VERSION 5.7 ;
  NOWIREEXTENSIONATPIN ON ;
  DIVIDERCHAR "/" ;
  BUSBITCHARS "[]" ;
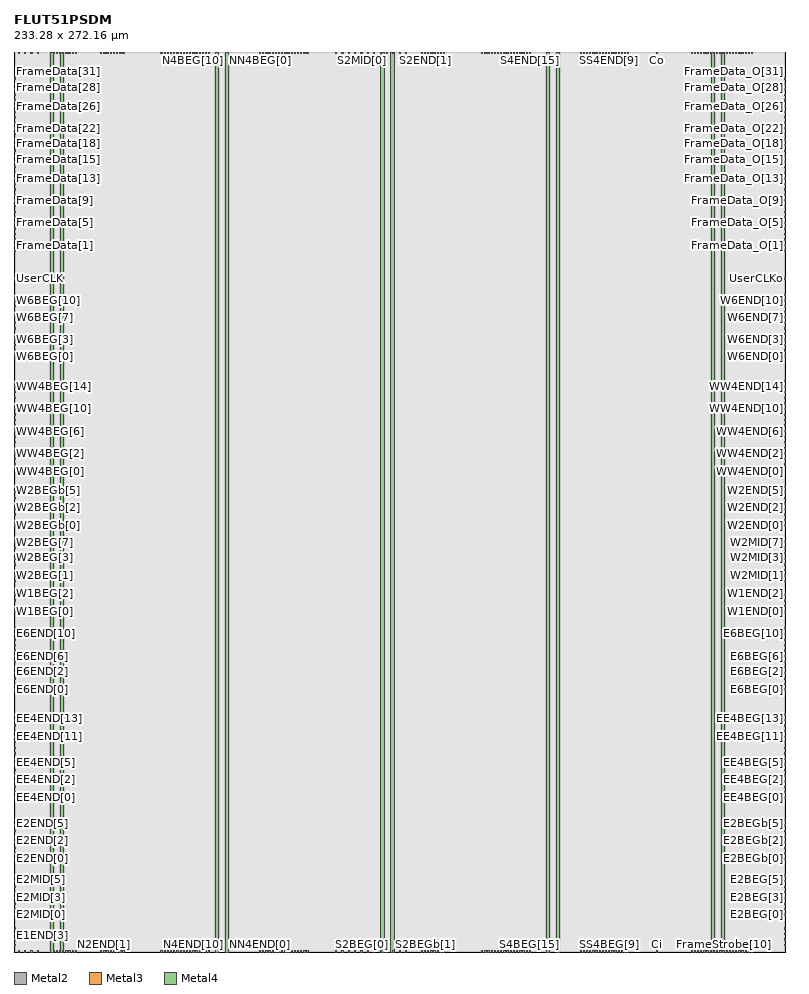
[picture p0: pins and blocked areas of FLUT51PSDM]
MACRO FLUT51PSDM
  CLASS BLOCK ;
  FOREIGN FLUT51PSDM ;
  ORIGIN 0.000 0.000 ;
  SIZE 233.280 BY 272.160 ;
  PIN Ci
    DIRECTION INPUT ;
    USE SIGNAL ;
    ANTENNAGATEAREA 0.241800 ;
    PORT
      LAYER Metal2 ;
        RECT 194.200 0.000 194.600 0.400 ;
    END
  END Ci
  PIN Co
    DIRECTION OUTPUT ;
    USE SIGNAL ;
    ANTENNADIFFAREA 2.647800 ;
    PORT
      LAYER Metal2 ;
        RECT 194.200 271.760 194.600 272.160 ;
    END
  END Co
  PIN E1BEG[0]
    DIRECTION OUTPUT ;
    USE SIGNAL ;
    ANTENNADIFFAREA 2.724000 ;
    PORT
      LAYER Metal3 ;
        RECT 232.880 1.900 233.280 2.300 ;
    END
  END E1BEG[0]
  PIN E1BEG[1]
    DIRECTION OUTPUT ;
    USE SIGNAL ;
    ANTENNADIFFAREA 2.724000 ;
    PORT
      LAYER Metal3 ;
        RECT 232.880 3.580 233.280 3.980 ;
    END
  END E1BEG[1]
  PIN E1BEG[2]
    DIRECTION OUTPUT ;
    USE SIGNAL ;
    ANTENNADIFFAREA 2.724000 ;
    PORT
      LAYER Metal3 ;
        RECT 232.880 5.260 233.280 5.660 ;
    END
  END E1BEG[2]
  PIN E1BEG[3]
    DIRECTION OUTPUT ;
    USE SIGNAL ;
    ANTENNADIFFAREA 2.724000 ;
    PORT
      LAYER Metal3 ;
        RECT 232.880 6.940 233.280 7.340 ;
    END
  END E1BEG[3]
  PIN E1END[0]
    DIRECTION INPUT ;
    USE SIGNAL ;
    ANTENNAGATEAREA 1.705600 ;
    PORT
      LAYER Metal3 ;
        RECT 0.000 1.900 0.400 2.300 ;
    END
  END E1END[0]
  PIN E1END[1]
    DIRECTION INPUT ;
    USE SIGNAL ;
    ANTENNAGATEAREA 2.132000 ;
    PORT
      LAYER Metal3 ;
        RECT 0.000 3.580 0.400 3.980 ;
    END
  END E1END[1]
  PIN E1END[2]
    DIRECTION INPUT ;
    USE SIGNAL ;
    ANTENNAGATEAREA 1.492400 ;
    PORT
      LAYER Metal3 ;
        RECT 0.000 5.260 0.400 5.660 ;
    END
  END E1END[2]
  PIN E1END[3]
    DIRECTION INPUT ;
    USE SIGNAL ;
    ANTENNAGATEAREA 2.145000 ;
    PORT
      LAYER Metal3 ;
        RECT 0.000 6.940 0.400 7.340 ;
    END
  END E1END[3]
  PIN E2BEG[0]
    DIRECTION OUTPUT ;
    USE SIGNAL ;
    ANTENNADIFFAREA 2.724000 ;
    PORT
      LAYER Metal3 ;
        RECT 232.880 11.140 233.280 11.540 ;
    END
  END E2BEG[0]
  PIN E2BEG[1]
    DIRECTION OUTPUT ;
    USE SIGNAL ;
    ANTENNADIFFAREA 2.724000 ;
    PORT
      LAYER Metal3 ;
        RECT 232.880 12.820 233.280 13.220 ;
    END
  END E2BEG[1]
  PIN E2BEG[2]
    DIRECTION OUTPUT ;
    USE SIGNAL ;
    ANTENNADIFFAREA 2.724000 ;
    PORT
      LAYER Metal3 ;
        RECT 232.880 14.500 233.280 14.900 ;
    END
  END E2BEG[2]
  PIN E2BEG[3]
    DIRECTION OUTPUT ;
    USE SIGNAL ;
    ANTENNADIFFAREA 2.724000 ;
    PORT
      LAYER Metal3 ;
        RECT 232.880 16.180 233.280 16.580 ;
    END
  END E2BEG[3]
  PIN E2BEG[4]
    DIRECTION OUTPUT ;
    USE SIGNAL ;
    ANTENNADIFFAREA 2.724000 ;
    PORT
      LAYER Metal3 ;
        RECT 232.880 17.860 233.280 18.260 ;
    END
  END E2BEG[4]
  PIN E2BEG[5]
    DIRECTION OUTPUT ;
    USE SIGNAL ;
    ANTENNADIFFAREA 2.724000 ;
    PORT
      LAYER Metal3 ;
        RECT 232.880 19.540 233.280 19.940 ;
    END
  END E2BEG[5]
  PIN E2BEG[6]
    DIRECTION OUTPUT ;
    USE SIGNAL ;
    ANTENNADIFFAREA 2.724000 ;
    PORT
      LAYER Metal3 ;
        RECT 232.880 21.220 233.280 21.620 ;
    END
  END E2BEG[6]
  PIN E2BEG[7]
    DIRECTION OUTPUT ;
    USE SIGNAL ;
    ANTENNADIFFAREA 2.724000 ;
    PORT
      LAYER Metal3 ;
        RECT 232.880 22.900 233.280 23.300 ;
    END
  END E2BEG[7]
  PIN E2BEGb[0]
    DIRECTION OUTPUT ;
    USE SIGNAL ;
    ANTENNADIFFAREA 2.724000 ;
    PORT
      LAYER Metal3 ;
        RECT 232.880 27.940 233.280 28.340 ;
    END
  END E2BEGb[0]
  PIN E2BEGb[1]
    DIRECTION OUTPUT ;
    USE SIGNAL ;
    ANTENNADIFFAREA 2.724000 ;
    PORT
      LAYER Metal3 ;
        RECT 232.880 29.620 233.280 30.020 ;
    END
  END E2BEGb[1]
  PIN E2BEGb[2]
    DIRECTION OUTPUT ;
    USE SIGNAL ;
    ANTENNADIFFAREA 2.724000 ;
    PORT
      LAYER Metal3 ;
        RECT 232.880 31.300 233.280 31.700 ;
    END
  END E2BEGb[2]
  PIN E2BEGb[3]
    DIRECTION OUTPUT ;
    USE SIGNAL ;
    ANTENNADIFFAREA 2.724000 ;
    PORT
      LAYER Metal3 ;
        RECT 232.880 32.980 233.280 33.380 ;
    END
  END E2BEGb[3]
  PIN E2BEGb[4]
    DIRECTION OUTPUT ;
    USE SIGNAL ;
    ANTENNADIFFAREA 2.724000 ;
    PORT
      LAYER Metal3 ;
        RECT 232.880 34.660 233.280 35.060 ;
    END
  END E2BEGb[4]
  PIN E2BEGb[5]
    DIRECTION OUTPUT ;
    USE SIGNAL ;
    ANTENNADIFFAREA 2.724000 ;
    PORT
      LAYER Metal3 ;
        RECT 232.880 36.340 233.280 36.740 ;
    END
  END E2BEGb[5]
  PIN E2BEGb[6]
    DIRECTION OUTPUT ;
    USE SIGNAL ;
    ANTENNADIFFAREA 2.724000 ;
    PORT
      LAYER Metal3 ;
        RECT 232.880 38.020 233.280 38.420 ;
    END
  END E2BEGb[6]
  PIN E2BEGb[7]
    DIRECTION OUTPUT ;
    USE SIGNAL ;
    ANTENNADIFFAREA 2.724000 ;
    PORT
      LAYER Metal3 ;
        RECT 232.880 39.700 233.280 40.100 ;
    END
  END E2BEGb[7]
  PIN E2END[0]
    DIRECTION INPUT ;
    USE SIGNAL ;
    ANTENNAGATEAREA 0.852800 ;
    PORT
      LAYER Metal3 ;
        RECT 0.000 27.940 0.400 28.340 ;
    END
  END E2END[0]
  PIN E2END[1]
    DIRECTION INPUT ;
    USE SIGNAL ;
    ANTENNAGATEAREA 1.279200 ;
    PORT
      LAYER Metal3 ;
        RECT 0.000 29.620 0.400 30.020 ;
    END
  END E2END[1]
  PIN E2END[2]
    DIRECTION INPUT ;
    USE SIGNAL ;
    ANTENNAGATEAREA 1.279200 ;
    PORT
      LAYER Metal3 ;
        RECT 0.000 31.300 0.400 31.700 ;
    END
  END E2END[2]
  PIN E2END[3]
    DIRECTION INPUT ;
    USE SIGNAL ;
    ANTENNAGATEAREA 1.492400 ;
    PORT
      LAYER Metal3 ;
        RECT 0.000 32.980 0.400 33.380 ;
    END
  END E2END[3]
  PIN E2END[4]
    DIRECTION INPUT ;
    USE SIGNAL ;
    ANTENNAGATEAREA 1.705600 ;
    PORT
      LAYER Metal3 ;
        RECT 0.000 34.660 0.400 35.060 ;
    END
  END E2END[4]
  PIN E2END[5]
    DIRECTION INPUT ;
    USE SIGNAL ;
    ANTENNAGATEAREA 1.492400 ;
    PORT
      LAYER Metal3 ;
        RECT 0.000 36.340 0.400 36.740 ;
    END
  END E2END[5]
  PIN E2END[6]
    DIRECTION INPUT ;
    USE SIGNAL ;
    ANTENNAGATEAREA 1.492400 ;
    PORT
      LAYER Metal3 ;
        RECT 0.000 38.020 0.400 38.420 ;
    END
  END E2END[6]
  PIN E2END[7]
    DIRECTION INPUT ;
    USE SIGNAL ;
    ANTENNAGATEAREA 1.066000 ;
    PORT
      LAYER Metal3 ;
        RECT 0.000 39.700 0.400 40.100 ;
    END
  END E2END[7]
  PIN E2MID[0]
    DIRECTION INPUT ;
    USE SIGNAL ;
    ANTENNAGATEAREA 2.099500 ;
    PORT
      LAYER Metal3 ;
        RECT 0.000 11.140 0.400 11.540 ;
    END
  END E2MID[0]
  PIN E2MID[1]
    DIRECTION INPUT ;
    USE SIGNAL ;
    ANTENNAGATEAREA 1.459900 ;
    PORT
      LAYER Metal3 ;
        RECT 0.000 12.820 0.400 13.220 ;
    END
  END E2MID[1]
  PIN E2MID[2]
    DIRECTION INPUT ;
    USE SIGNAL ;
    ANTENNAGATEAREA 1.673100 ;
    PORT
      LAYER Metal3 ;
        RECT 0.000 14.500 0.400 14.900 ;
    END
  END E2MID[2]
  PIN E2MID[3]
    DIRECTION INPUT ;
    USE SIGNAL ;
    ANTENNAGATEAREA 2.312700 ;
    PORT
      LAYER Metal3 ;
        RECT 0.000 16.180 0.400 16.580 ;
    END
  END E2MID[3]
  PIN E2MID[4]
    DIRECTION INPUT ;
    USE SIGNAL ;
    ANTENNAGATEAREA 1.673100 ;
    PORT
      LAYER Metal3 ;
        RECT 0.000 17.860 0.400 18.260 ;
    END
  END E2MID[4]
  PIN E2MID[5]
    DIRECTION INPUT ;
    USE SIGNAL ;
    ANTENNAGATEAREA 1.459900 ;
    PORT
      LAYER Metal3 ;
        RECT 0.000 19.540 0.400 19.940 ;
    END
  END E2MID[5]
  PIN E2MID[6]
    DIRECTION INPUT ;
    USE SIGNAL ;
    ANTENNAGATEAREA 1.699100 ;
    PORT
      LAYER Metal3 ;
        RECT 0.000 21.220 0.400 21.620 ;
    END
  END E2MID[6]
  PIN E2MID[7]
    DIRECTION INPUT ;
    USE SIGNAL ;
    ANTENNAGATEAREA 1.459900 ;
    PORT
      LAYER Metal3 ;
        RECT 0.000 22.900 0.400 23.300 ;
    END
  END E2MID[7]
  PIN E6BEG[0]
    DIRECTION OUTPUT ;
    USE SIGNAL ;
    ANTENNADIFFAREA 2.724000 ;
    PORT
      LAYER Metal3 ;
        RECT 232.880 79.180 233.280 79.580 ;
    END
  END E6BEG[0]
  PIN E6BEG[10]
    DIRECTION OUTPUT ;
    USE SIGNAL ;
    ANTENNADIFFAREA 2.724000 ;
    PORT
      LAYER Metal3 ;
        RECT 232.880 95.980 233.280 96.380 ;
    END
  END E6BEG[10]
  PIN E6BEG[11]
    DIRECTION OUTPUT ;
    USE SIGNAL ;
    ANTENNADIFFAREA 2.724000 ;
    PORT
      LAYER Metal3 ;
        RECT 232.880 97.660 233.280 98.060 ;
    END
  END E6BEG[11]
  PIN E6BEG[1]
    DIRECTION OUTPUT ;
    USE SIGNAL ;
    ANTENNADIFFAREA 2.724000 ;
    PORT
      LAYER Metal3 ;
        RECT 232.880 80.860 233.280 81.260 ;
    END
  END E6BEG[1]
  PIN E6BEG[2]
    DIRECTION OUTPUT ;
    USE SIGNAL ;
    ANTENNADIFFAREA 2.724000 ;
    PORT
      LAYER Metal3 ;
        RECT 232.880 82.540 233.280 82.940 ;
    END
  END E6BEG[2]
  PIN E6BEG[3]
    DIRECTION OUTPUT ;
    USE SIGNAL ;
    ANTENNADIFFAREA 2.724000 ;
    PORT
      LAYER Metal3 ;
        RECT 232.880 84.220 233.280 84.620 ;
    END
  END E6BEG[3]
  PIN E6BEG[4]
    DIRECTION OUTPUT ;
    USE SIGNAL ;
    ANTENNADIFFAREA 2.724000 ;
    PORT
      LAYER Metal3 ;
        RECT 232.880 85.900 233.280 86.300 ;
    END
  END E6BEG[4]
  PIN E6BEG[5]
    DIRECTION OUTPUT ;
    USE SIGNAL ;
    ANTENNADIFFAREA 2.724000 ;
    PORT
      LAYER Metal3 ;
        RECT 232.880 87.580 233.280 87.980 ;
    END
  END E6BEG[5]
  PIN E6BEG[6]
    DIRECTION OUTPUT ;
    USE SIGNAL ;
    ANTENNADIFFAREA 2.724000 ;
    PORT
      LAYER Metal3 ;
        RECT 232.880 89.260 233.280 89.660 ;
    END
  END E6BEG[6]
  PIN E6BEG[7]
    DIRECTION OUTPUT ;
    USE SIGNAL ;
    ANTENNADIFFAREA 2.724000 ;
    PORT
      LAYER Metal3 ;
        RECT 232.880 90.940 233.280 91.340 ;
    END
  END E6BEG[7]
  PIN E6BEG[8]
    DIRECTION OUTPUT ;
    USE SIGNAL ;
    ANTENNADIFFAREA 2.724000 ;
    PORT
      LAYER Metal3 ;
        RECT 232.880 92.620 233.280 93.020 ;
    END
  END E6BEG[8]
  PIN E6BEG[9]
    DIRECTION OUTPUT ;
    USE SIGNAL ;
    ANTENNADIFFAREA 2.724000 ;
    PORT
      LAYER Metal3 ;
        RECT 232.880 94.300 233.280 94.700 ;
    END
  END E6BEG[9]
  PIN E6END[0]
    DIRECTION INPUT ;
    USE SIGNAL ;
    ANTENNAGATEAREA 1.918800 ;
    PORT
      LAYER Metal3 ;
        RECT 0.000 79.180 0.400 79.580 ;
    END
  END E6END[0]
  PIN E6END[10]
    DIRECTION INPUT ;
    USE SIGNAL ;
    ANTENNAGATEAREA 0.180700 ;
    PORT
      LAYER Metal3 ;
        RECT 0.000 95.980 0.400 96.380 ;
    END
  END E6END[10]
  PIN E6END[11]
    DIRECTION INPUT ;
    USE SIGNAL ;
    ANTENNAGATEAREA 0.180700 ;
    PORT
      LAYER Metal3 ;
        RECT 0.000 97.660 0.400 98.060 ;
    END
  END E6END[11]
  PIN E6END[1]
    DIRECTION INPUT ;
    USE SIGNAL ;
    ANTENNAGATEAREA 2.345200 ;
    PORT
      LAYER Metal3 ;
        RECT 0.000 80.860 0.400 81.260 ;
    END
  END E6END[1]
  PIN E6END[2]
    DIRECTION INPUT ;
    USE SIGNAL ;
    ANTENNAGATEAREA 0.180700 ;
    PORT
      LAYER Metal3 ;
        RECT 0.000 82.540 0.400 82.940 ;
    END
  END E6END[2]
  PIN E6END[3]
    DIRECTION INPUT ;
    USE SIGNAL ;
    ANTENNAGATEAREA 0.180700 ;
    PORT
      LAYER Metal3 ;
        RECT 0.000 84.220 0.400 84.620 ;
    END
  END E6END[3]
  PIN E6END[4]
    DIRECTION INPUT ;
    USE SIGNAL ;
    ANTENNAGATEAREA 0.180700 ;
    PORT
      LAYER Metal3 ;
        RECT 0.000 85.900 0.400 86.300 ;
    END
  END E6END[4]
  PIN E6END[5]
    DIRECTION INPUT ;
    USE SIGNAL ;
    ANTENNAGATEAREA 0.180700 ;
    PORT
      LAYER Metal3 ;
        RECT 0.000 87.580 0.400 87.980 ;
    END
  END E6END[5]
  PIN E6END[6]
    DIRECTION INPUT ;
    USE SIGNAL ;
    ANTENNAGATEAREA 0.180700 ;
    PORT
      LAYER Metal3 ;
        RECT 0.000 89.260 0.400 89.660 ;
    END
  END E6END[6]
  PIN E6END[7]
    DIRECTION INPUT ;
    USE SIGNAL ;
    ANTENNAGATEAREA 0.180700 ;
    PORT
      LAYER Metal3 ;
        RECT 0.000 90.940 0.400 91.340 ;
    END
  END E6END[7]
  PIN E6END[8]
    DIRECTION INPUT ;
    USE SIGNAL ;
    ANTENNAGATEAREA 0.180700 ;
    PORT
      LAYER Metal3 ;
        RECT 0.000 92.620 0.400 93.020 ;
    END
  END E6END[8]
  PIN E6END[9]
    DIRECTION INPUT ;
    USE SIGNAL ;
    ANTENNAGATEAREA 0.180700 ;
    PORT
      LAYER Metal3 ;
        RECT 0.000 94.300 0.400 94.700 ;
    END
  END E6END[9]
  PIN EE4BEG[0]
    DIRECTION OUTPUT ;
    USE SIGNAL ;
    ANTENNADIFFAREA 2.724000 ;
    PORT
      LAYER Metal3 ;
        RECT 232.880 46.420 233.280 46.820 ;
    END
  END EE4BEG[0]
  PIN EE4BEG[10]
    DIRECTION OUTPUT ;
    USE SIGNAL ;
    ANTENNADIFFAREA 2.724000 ;
    PORT
      LAYER Metal3 ;
        RECT 232.880 63.220 233.280 63.620 ;
    END
  END EE4BEG[10]
  PIN EE4BEG[11]
    DIRECTION OUTPUT ;
    USE SIGNAL ;
    ANTENNADIFFAREA 2.724000 ;
    PORT
      LAYER Metal3 ;
        RECT 232.880 64.900 233.280 65.300 ;
    END
  END EE4BEG[11]
  PIN EE4BEG[12]
    DIRECTION OUTPUT ;
    USE SIGNAL ;
    ANTENNADIFFAREA 2.724000 ;
    PORT
      LAYER Metal3 ;
        RECT 232.880 66.580 233.280 66.980 ;
    END
  END EE4BEG[12]
  PIN EE4BEG[13]
    DIRECTION OUTPUT ;
    USE SIGNAL ;
    ANTENNADIFFAREA 2.724000 ;
    PORT
      LAYER Metal3 ;
        RECT 232.880 68.260 233.280 68.660 ;
    END
  END EE4BEG[13]
  PIN EE4BEG[14]
    DIRECTION OUTPUT ;
    USE SIGNAL ;
    ANTENNADIFFAREA 2.724000 ;
    PORT
      LAYER Metal3 ;
        RECT 232.880 69.940 233.280 70.340 ;
    END
  END EE4BEG[14]
  PIN EE4BEG[15]
    DIRECTION OUTPUT ;
    USE SIGNAL ;
    ANTENNADIFFAREA 2.724000 ;
    PORT
      LAYER Metal3 ;
        RECT 232.880 71.620 233.280 72.020 ;
    END
  END EE4BEG[15]
  PIN EE4BEG[1]
    DIRECTION OUTPUT ;
    USE SIGNAL ;
    ANTENNADIFFAREA 2.724000 ;
    PORT
      LAYER Metal3 ;
        RECT 232.880 48.100 233.280 48.500 ;
    END
  END EE4BEG[1]
  PIN EE4BEG[2]
    DIRECTION OUTPUT ;
    USE SIGNAL ;
    ANTENNADIFFAREA 2.724000 ;
    PORT
      LAYER Metal3 ;
        RECT 232.880 49.780 233.280 50.180 ;
    END
  END EE4BEG[2]
  PIN EE4BEG[3]
    DIRECTION OUTPUT ;
    USE SIGNAL ;
    ANTENNADIFFAREA 2.724000 ;
    PORT
      LAYER Metal3 ;
        RECT 232.880 51.460 233.280 51.860 ;
    END
  END EE4BEG[3]
  PIN EE4BEG[4]
    DIRECTION OUTPUT ;
    USE SIGNAL ;
    ANTENNADIFFAREA 2.724000 ;
    PORT
      LAYER Metal3 ;
        RECT 232.880 53.140 233.280 53.540 ;
    END
  END EE4BEG[4]
  PIN EE4BEG[5]
    DIRECTION OUTPUT ;
    USE SIGNAL ;
    ANTENNADIFFAREA 2.724000 ;
    PORT
      LAYER Metal3 ;
        RECT 232.880 54.820 233.280 55.220 ;
    END
  END EE4BEG[5]
  PIN EE4BEG[6]
    DIRECTION OUTPUT ;
    USE SIGNAL ;
    ANTENNADIFFAREA 2.724000 ;
    PORT
      LAYER Metal3 ;
        RECT 232.880 56.500 233.280 56.900 ;
    END
  END EE4BEG[6]
  PIN EE4BEG[7]
    DIRECTION OUTPUT ;
    USE SIGNAL ;
    ANTENNADIFFAREA 2.724000 ;
    PORT
      LAYER Metal3 ;
        RECT 232.880 58.180 233.280 58.580 ;
    END
  END EE4BEG[7]
  PIN EE4BEG[8]
    DIRECTION OUTPUT ;
    USE SIGNAL ;
    ANTENNADIFFAREA 2.724000 ;
    PORT
      LAYER Metal3 ;
        RECT 232.880 59.860 233.280 60.260 ;
    END
  END EE4BEG[8]
  PIN EE4BEG[9]
    DIRECTION OUTPUT ;
    USE SIGNAL ;
    ANTENNADIFFAREA 2.724000 ;
    PORT
      LAYER Metal3 ;
        RECT 232.880 61.540 233.280 61.940 ;
    END
  END EE4BEG[9]
  PIN EE4END[0]
    DIRECTION INPUT ;
    USE SIGNAL ;
    ANTENNAGATEAREA 1.918800 ;
    PORT
      LAYER Metal3 ;
        RECT 0.000 46.420 0.400 46.820 ;
    END
  END EE4END[0]
  PIN EE4END[10]
    DIRECTION INPUT ;
    USE SIGNAL ;
    ANTENNAGATEAREA 0.180700 ;
    PORT
      LAYER Metal3 ;
        RECT 0.000 63.220 0.400 63.620 ;
    END
  END EE4END[10]
  PIN EE4END[11]
    DIRECTION INPUT ;
    USE SIGNAL ;
    ANTENNAGATEAREA 0.180700 ;
    PORT
      LAYER Metal3 ;
        RECT 0.000 64.900 0.400 65.300 ;
    END
  END EE4END[11]
  PIN EE4END[12]
    DIRECTION INPUT ;
    USE SIGNAL ;
    ANTENNAGATEAREA 0.180700 ;
    PORT
      LAYER Metal3 ;
        RECT 0.000 66.580 0.400 66.980 ;
    END
  END EE4END[12]
  PIN EE4END[13]
    DIRECTION INPUT ;
    USE SIGNAL ;
    ANTENNAGATEAREA 0.180700 ;
    PORT
      LAYER Metal3 ;
        RECT 0.000 68.260 0.400 68.660 ;
    END
  END EE4END[13]
  PIN EE4END[14]
    DIRECTION INPUT ;
    USE SIGNAL ;
    ANTENNAGATEAREA 0.180700 ;
    PORT
      LAYER Metal3 ;
        RECT 0.000 69.940 0.400 70.340 ;
    END
  END EE4END[14]
  PIN EE4END[15]
    DIRECTION INPUT ;
    USE SIGNAL ;
    ANTENNAGATEAREA 0.180700 ;
    PORT
      LAYER Metal3 ;
        RECT 0.000 71.620 0.400 72.020 ;
    END
  END EE4END[15]
  PIN EE4END[1]
    DIRECTION INPUT ;
    USE SIGNAL ;
    ANTENNAGATEAREA 1.492400 ;
    PORT
      LAYER Metal3 ;
        RECT 0.000 48.100 0.400 48.500 ;
    END
  END EE4END[1]
  PIN EE4END[2]
    DIRECTION INPUT ;
    USE SIGNAL ;
    ANTENNAGATEAREA 1.705600 ;
    PORT
      LAYER Metal3 ;
        RECT 0.000 49.780 0.400 50.180 ;
    END
  END EE4END[2]
  PIN EE4END[3]
    DIRECTION INPUT ;
    USE SIGNAL ;
    ANTENNAGATEAREA 1.492400 ;
    PORT
      LAYER Metal3 ;
        RECT 0.000 51.460 0.400 51.860 ;
    END
  END EE4END[3]
  PIN EE4END[4]
    DIRECTION INPUT ;
    USE SIGNAL ;
    ANTENNAGATEAREA 0.180700 ;
    PORT
      LAYER Metal3 ;
        RECT 0.000 53.140 0.400 53.540 ;
    END
  END EE4END[4]
  PIN EE4END[5]
    DIRECTION INPUT ;
    USE SIGNAL ;
    ANTENNAGATEAREA 0.180700 ;
    PORT
      LAYER Metal3 ;
        RECT 0.000 54.820 0.400 55.220 ;
    END
  END EE4END[5]
  PIN EE4END[6]
    DIRECTION INPUT ;
    USE SIGNAL ;
    ANTENNAGATEAREA 0.180700 ;
    PORT
      LAYER Metal3 ;
        RECT 0.000 56.500 0.400 56.900 ;
    END
  END EE4END[6]
  PIN EE4END[7]
    DIRECTION INPUT ;
    USE SIGNAL ;
    ANTENNAGATEAREA 0.180700 ;
    PORT
      LAYER Metal3 ;
        RECT 0.000 58.180 0.400 58.580 ;
    END
  END EE4END[7]
  PIN EE4END[8]
    DIRECTION INPUT ;
    USE SIGNAL ;
    ANTENNAGATEAREA 0.180700 ;
    PORT
      LAYER Metal3 ;
        RECT 0.000 59.860 0.400 60.260 ;
    END
  END EE4END[8]
  PIN EE4END[9]
    DIRECTION INPUT ;
    USE SIGNAL ;
    ANTENNAGATEAREA 0.180700 ;
    PORT
      LAYER Metal3 ;
        RECT 0.000 61.540 0.400 61.940 ;
    END
  END EE4END[9]
  PIN FrameData[0]
    DIRECTION INPUT ;
    USE SIGNAL ;
    ANTENNAGATEAREA 6.143800 ;
    PORT
      LAYER Metal3 ;
        RECT 0.000 211.900 0.400 212.300 ;
    END
  END FrameData[0]
  PIN FrameData[10]
    DIRECTION INPUT ;
    USE SIGNAL ;
    ANTENNAGATEAREA 6.324500 ;
    PORT
      LAYER Metal3 ;
        RECT 0.000 228.700 0.400 229.100 ;
    END
  END FrameData[10]
  PIN FrameData[11]
    DIRECTION INPUT ;
    USE SIGNAL ;
    ANTENNAGATEAREA 6.324500 ;
    PORT
      LAYER Metal3 ;
        RECT 0.000 230.380 0.400 230.780 ;
    END
  END FrameData[11]
  PIN FrameData[12]
    DIRECTION INPUT ;
    USE SIGNAL ;
    ANTENNAGATEAREA 6.324500 ;
    PORT
      LAYER Metal3 ;
        RECT 0.000 232.060 0.400 232.460 ;
    END
  END FrameData[12]
  PIN FrameData[13]
    DIRECTION INPUT ;
    USE SIGNAL ;
    ANTENNAGATEAREA 6.324500 ;
    PORT
      LAYER Metal3 ;
        RECT 0.000 233.740 0.400 234.140 ;
    END
  END FrameData[13]
  PIN FrameData[14]
    DIRECTION INPUT ;
    USE SIGNAL ;
    ANTENNAGATEAREA 6.324500 ;
    PORT
      LAYER Metal3 ;
        RECT 0.000 235.420 0.400 235.820 ;
    END
  END FrameData[14]
  PIN FrameData[15]
    DIRECTION INPUT ;
    USE SIGNAL ;
    ANTENNAGATEAREA 6.324500 ;
    PORT
      LAYER Metal3 ;
        RECT 0.000 237.100 0.400 237.500 ;
    END
  END FrameData[15]
  PIN FrameData[16]
    DIRECTION INPUT ;
    USE SIGNAL ;
    ANTENNAGATEAREA 6.324500 ;
    PORT
      LAYER Metal3 ;
        RECT 0.000 238.780 0.400 239.180 ;
    END
  END FrameData[16]
  PIN FrameData[17]
    DIRECTION INPUT ;
    USE SIGNAL ;
    ANTENNAGATEAREA 6.324500 ;
    PORT
      LAYER Metal3 ;
        RECT 0.000 240.460 0.400 240.860 ;
    END
  END FrameData[17]
  PIN FrameData[18]
    DIRECTION INPUT ;
    USE SIGNAL ;
    ANTENNAGATEAREA 6.324500 ;
    PORT
      LAYER Metal3 ;
        RECT 0.000 242.140 0.400 242.540 ;
    END
  END FrameData[18]
  PIN FrameData[19]
    DIRECTION INPUT ;
    USE SIGNAL ;
    ANTENNAGATEAREA 6.324500 ;
    PORT
      LAYER Metal3 ;
        RECT 0.000 243.820 0.400 244.220 ;
    END
  END FrameData[19]
  PIN FrameData[1]
    DIRECTION INPUT ;
    USE SIGNAL ;
    ANTENNAGATEAREA 6.143800 ;
    PORT
      LAYER Metal3 ;
        RECT 0.000 213.580 0.400 213.980 ;
    END
  END FrameData[1]
  PIN FrameData[20]
    DIRECTION INPUT ;
    USE SIGNAL ;
    ANTENNAGATEAREA 6.324500 ;
    PORT
      LAYER Metal3 ;
        RECT 0.000 245.500 0.400 245.900 ;
    END
  END FrameData[20]
  PIN FrameData[21]
    DIRECTION INPUT ;
    USE SIGNAL ;
    ANTENNAGATEAREA 6.324500 ;
    PORT
      LAYER Metal3 ;
        RECT 0.000 247.180 0.400 247.580 ;
    END
  END FrameData[21]
  PIN FrameData[22]
    DIRECTION INPUT ;
    USE SIGNAL ;
    ANTENNAGATEAREA 6.324500 ;
    PORT
      LAYER Metal3 ;
        RECT 0.000 248.860 0.400 249.260 ;
    END
  END FrameData[22]
  PIN FrameData[23]
    DIRECTION INPUT ;
    USE SIGNAL ;
    ANTENNAGATEAREA 6.324500 ;
    PORT
      LAYER Metal3 ;
        RECT 0.000 250.540 0.400 250.940 ;
    END
  END FrameData[23]
  PIN FrameData[24]
    DIRECTION INPUT ;
    USE SIGNAL ;
    ANTENNAGATEAREA 6.324500 ;
    PORT
      LAYER Metal3 ;
        RECT 0.000 252.220 0.400 252.620 ;
    END
  END FrameData[24]
  PIN FrameData[25]
    DIRECTION INPUT ;
    USE SIGNAL ;
    ANTENNAGATEAREA 6.324500 ;
    PORT
      LAYER Metal3 ;
        RECT 0.000 253.900 0.400 254.300 ;
    END
  END FrameData[25]
  PIN FrameData[26]
    DIRECTION INPUT ;
    USE SIGNAL ;
    ANTENNAGATEAREA 6.324500 ;
    PORT
      LAYER Metal3 ;
        RECT 0.000 255.580 0.400 255.980 ;
    END
  END FrameData[26]
  PIN FrameData[27]
    DIRECTION INPUT ;
    USE SIGNAL ;
    ANTENNAGATEAREA 6.324500 ;
    PORT
      LAYER Metal3 ;
        RECT 0.000 257.260 0.400 257.660 ;
    END
  END FrameData[27]
  PIN FrameData[28]
    DIRECTION INPUT ;
    USE SIGNAL ;
    ANTENNAGATEAREA 6.324500 ;
    PORT
      LAYER Metal3 ;
        RECT 0.000 258.940 0.400 259.340 ;
    END
  END FrameData[28]
  PIN FrameData[29]
    DIRECTION INPUT ;
    USE SIGNAL ;
    ANTENNAGATEAREA 6.324500 ;
    PORT
      LAYER Metal3 ;
        RECT 0.000 260.620 0.400 261.020 ;
    END
  END FrameData[29]
  PIN FrameData[2]
    DIRECTION INPUT ;
    USE SIGNAL ;
    ANTENNAGATEAREA 6.143800 ;
    PORT
      LAYER Metal3 ;
        RECT 0.000 215.260 0.400 215.660 ;
    END
  END FrameData[2]
  PIN FrameData[30]
    DIRECTION INPUT ;
    USE SIGNAL ;
    ANTENNAGATEAREA 6.324500 ;
    PORT
      LAYER Metal3 ;
        RECT 0.000 262.300 0.400 262.700 ;
    END
  END FrameData[30]
  PIN FrameData[31]
    DIRECTION INPUT ;
    USE SIGNAL ;
    ANTENNAGATEAREA 6.324500 ;
    PORT
      LAYER Metal3 ;
        RECT 0.000 263.980 0.400 264.380 ;
    END
  END FrameData[31]
  PIN FrameData[3]
    DIRECTION INPUT ;
    USE SIGNAL ;
    ANTENNAGATEAREA 6.143800 ;
    PORT
      LAYER Metal3 ;
        RECT 0.000 216.940 0.400 217.340 ;
    END
  END FrameData[3]
  PIN FrameData[4]
    DIRECTION INPUT ;
    USE SIGNAL ;
    ANTENNAGATEAREA 6.143800 ;
    PORT
      LAYER Metal3 ;
        RECT 0.000 218.620 0.400 219.020 ;
    END
  END FrameData[4]
  PIN FrameData[5]
    DIRECTION INPUT ;
    USE SIGNAL ;
    ANTENNAGATEAREA 6.143800 ;
    PORT
      LAYER Metal3 ;
        RECT 0.000 220.300 0.400 220.700 ;
    END
  END FrameData[5]
  PIN FrameData[6]
    DIRECTION INPUT ;
    USE SIGNAL ;
    ANTENNAGATEAREA 6.143800 ;
    PORT
      LAYER Metal3 ;
        RECT 0.000 221.980 0.400 222.380 ;
    END
  END FrameData[6]
  PIN FrameData[7]
    DIRECTION INPUT ;
    USE SIGNAL ;
    ANTENNAGATEAREA 6.143800 ;
    PORT
      LAYER Metal3 ;
        RECT 0.000 223.660 0.400 224.060 ;
    END
  END FrameData[7]
  PIN FrameData[8]
    DIRECTION INPUT ;
    USE SIGNAL ;
    ANTENNAGATEAREA 6.324500 ;
    PORT
      LAYER Metal3 ;
        RECT 0.000 225.340 0.400 225.740 ;
    END
  END FrameData[8]
  PIN FrameData[9]
    DIRECTION INPUT ;
    USE SIGNAL ;
    ANTENNAGATEAREA 6.324500 ;
    PORT
      LAYER Metal3 ;
        RECT 0.000 227.020 0.400 227.420 ;
    END
  END FrameData[9]
  PIN FrameData_O[0]
    DIRECTION OUTPUT ;
    USE SIGNAL ;
    ANTENNADIFFAREA 2.724000 ;
    PORT
      LAYER Metal3 ;
        RECT 232.880 211.900 233.280 212.300 ;
    END
  END FrameData_O[0]
  PIN FrameData_O[10]
    DIRECTION OUTPUT ;
    USE SIGNAL ;
    ANTENNADIFFAREA 2.724000 ;
    PORT
      LAYER Metal3 ;
        RECT 232.880 228.700 233.280 229.100 ;
    END
  END FrameData_O[10]
  PIN FrameData_O[11]
    DIRECTION OUTPUT ;
    USE SIGNAL ;
    ANTENNADIFFAREA 2.724000 ;
    PORT
      LAYER Metal3 ;
        RECT 232.880 230.380 233.280 230.780 ;
    END
  END FrameData_O[11]
  PIN FrameData_O[12]
    DIRECTION OUTPUT ;
    USE SIGNAL ;
    ANTENNADIFFAREA 2.724000 ;
    PORT
      LAYER Metal3 ;
        RECT 232.880 232.060 233.280 232.460 ;
    END
  END FrameData_O[12]
  PIN FrameData_O[13]
    DIRECTION OUTPUT ;
    USE SIGNAL ;
    ANTENNADIFFAREA 2.724000 ;
    PORT
      LAYER Metal3 ;
        RECT 232.880 233.740 233.280 234.140 ;
    END
  END FrameData_O[13]
  PIN FrameData_O[14]
    DIRECTION OUTPUT ;
    USE SIGNAL ;
    ANTENNADIFFAREA 2.724000 ;
    PORT
      LAYER Metal3 ;
        RECT 232.880 235.420 233.280 235.820 ;
    END
  END FrameData_O[14]
  PIN FrameData_O[15]
    DIRECTION OUTPUT ;
    USE SIGNAL ;
    ANTENNADIFFAREA 2.724000 ;
    PORT
      LAYER Metal3 ;
        RECT 232.880 237.100 233.280 237.500 ;
    END
  END FrameData_O[15]
  PIN FrameData_O[16]
    DIRECTION OUTPUT ;
    USE SIGNAL ;
    ANTENNADIFFAREA 2.724000 ;
    PORT
      LAYER Metal3 ;
        RECT 232.880 238.780 233.280 239.180 ;
    END
  END FrameData_O[16]
  PIN FrameData_O[17]
    DIRECTION OUTPUT ;
    USE SIGNAL ;
    ANTENNADIFFAREA 2.724000 ;
    PORT
      LAYER Metal3 ;
        RECT 232.880 240.460 233.280 240.860 ;
    END
  END FrameData_O[17]
  PIN FrameData_O[18]
    DIRECTION OUTPUT ;
    USE SIGNAL ;
    ANTENNADIFFAREA 2.724000 ;
    PORT
      LAYER Metal3 ;
        RECT 232.880 242.140 233.280 242.540 ;
    END
  END FrameData_O[18]
  PIN FrameData_O[19]
    DIRECTION OUTPUT ;
    USE SIGNAL ;
    ANTENNADIFFAREA 2.724000 ;
    PORT
      LAYER Metal3 ;
        RECT 232.880 243.820 233.280 244.220 ;
    END
  END FrameData_O[19]
  PIN FrameData_O[1]
    DIRECTION OUTPUT ;
    USE SIGNAL ;
    ANTENNADIFFAREA 2.724000 ;
    PORT
      LAYER Metal3 ;
        RECT 232.880 213.580 233.280 213.980 ;
    END
  END FrameData_O[1]
  PIN FrameData_O[20]
    DIRECTION OUTPUT ;
    USE SIGNAL ;
    ANTENNADIFFAREA 2.724000 ;
    PORT
      LAYER Metal3 ;
        RECT 232.880 245.500 233.280 245.900 ;
    END
  END FrameData_O[20]
  PIN FrameData_O[21]
    DIRECTION OUTPUT ;
    USE SIGNAL ;
    ANTENNADIFFAREA 2.724000 ;
    PORT
      LAYER Metal3 ;
        RECT 232.880 247.180 233.280 247.580 ;
    END
  END FrameData_O[21]
  PIN FrameData_O[22]
    DIRECTION OUTPUT ;
    USE SIGNAL ;
    ANTENNADIFFAREA 2.724000 ;
    PORT
      LAYER Metal3 ;
        RECT 232.880 248.860 233.280 249.260 ;
    END
  END FrameData_O[22]
  PIN FrameData_O[23]
    DIRECTION OUTPUT ;
    USE SIGNAL ;
    ANTENNADIFFAREA 2.724000 ;
    PORT
      LAYER Metal3 ;
        RECT 232.880 250.540 233.280 250.940 ;
    END
  END FrameData_O[23]
  PIN FrameData_O[24]
    DIRECTION OUTPUT ;
    USE SIGNAL ;
    ANTENNADIFFAREA 2.724000 ;
    PORT
      LAYER Metal3 ;
        RECT 232.880 252.220 233.280 252.620 ;
    END
  END FrameData_O[24]
  PIN FrameData_O[25]
    DIRECTION OUTPUT ;
    USE SIGNAL ;
    ANTENNADIFFAREA 2.724000 ;
    PORT
      LAYER Metal3 ;
        RECT 232.880 253.900 233.280 254.300 ;
    END
  END FrameData_O[25]
  PIN FrameData_O[26]
    DIRECTION OUTPUT ;
    USE SIGNAL ;
    ANTENNADIFFAREA 2.724000 ;
    PORT
      LAYER Metal3 ;
        RECT 232.880 255.580 233.280 255.980 ;
    END
  END FrameData_O[26]
  PIN FrameData_O[27]
    DIRECTION OUTPUT ;
    USE SIGNAL ;
    ANTENNADIFFAREA 2.724000 ;
    PORT
      LAYER Metal3 ;
        RECT 232.880 257.260 233.280 257.660 ;
    END
  END FrameData_O[27]
  PIN FrameData_O[28]
    DIRECTION OUTPUT ;
    USE SIGNAL ;
    ANTENNADIFFAREA 2.724000 ;
    PORT
      LAYER Metal3 ;
        RECT 232.880 258.940 233.280 259.340 ;
    END
  END FrameData_O[28]
  PIN FrameData_O[29]
    DIRECTION OUTPUT ;
    USE SIGNAL ;
    ANTENNADIFFAREA 2.724000 ;
    PORT
      LAYER Metal3 ;
        RECT 232.880 260.620 233.280 261.020 ;
    END
  END FrameData_O[29]
  PIN FrameData_O[2]
    DIRECTION OUTPUT ;
    USE SIGNAL ;
    ANTENNADIFFAREA 2.724000 ;
    PORT
      LAYER Metal3 ;
        RECT 232.880 215.260 233.280 215.660 ;
    END
  END FrameData_O[2]
  PIN FrameData_O[30]
    DIRECTION OUTPUT ;
    USE SIGNAL ;
    ANTENNADIFFAREA 2.724000 ;
    PORT
      LAYER Metal3 ;
        RECT 232.880 262.300 233.280 262.700 ;
    END
  END FrameData_O[30]
  PIN FrameData_O[31]
    DIRECTION OUTPUT ;
    USE SIGNAL ;
    ANTENNADIFFAREA 2.724000 ;
    PORT
      LAYER Metal3 ;
        RECT 232.880 263.980 233.280 264.380 ;
    END
  END FrameData_O[31]
  PIN FrameData_O[3]
    DIRECTION OUTPUT ;
    USE SIGNAL ;
    ANTENNADIFFAREA 2.724000 ;
    PORT
      LAYER Metal3 ;
        RECT 232.880 216.940 233.280 217.340 ;
    END
  END FrameData_O[3]
  PIN FrameData_O[4]
    DIRECTION OUTPUT ;
    USE SIGNAL ;
    ANTENNADIFFAREA 2.724000 ;
    PORT
      LAYER Metal3 ;
        RECT 232.880 218.620 233.280 219.020 ;
    END
  END FrameData_O[4]
  PIN FrameData_O[5]
    DIRECTION OUTPUT ;
    USE SIGNAL ;
    ANTENNADIFFAREA 2.724000 ;
    PORT
      LAYER Metal3 ;
        RECT 232.880 220.300 233.280 220.700 ;
    END
  END FrameData_O[5]
  PIN FrameData_O[6]
    DIRECTION OUTPUT ;
    USE SIGNAL ;
    ANTENNADIFFAREA 2.724000 ;
    PORT
      LAYER Metal3 ;
        RECT 232.880 221.980 233.280 222.380 ;
    END
  END FrameData_O[6]
  PIN FrameData_O[7]
    DIRECTION OUTPUT ;
    USE SIGNAL ;
    ANTENNADIFFAREA 2.724000 ;
    PORT
      LAYER Metal3 ;
        RECT 232.880 223.660 233.280 224.060 ;
    END
  END FrameData_O[7]
  PIN FrameData_O[8]
    DIRECTION OUTPUT ;
    USE SIGNAL ;
    ANTENNADIFFAREA 2.724000 ;
    PORT
      LAYER Metal3 ;
        RECT 232.880 225.340 233.280 225.740 ;
    END
  END FrameData_O[8]
  PIN FrameData_O[9]
    DIRECTION OUTPUT ;
    USE SIGNAL ;
    ANTENNADIFFAREA 2.724000 ;
    PORT
      LAYER Metal3 ;
        RECT 232.880 227.020 233.280 227.420 ;
    END
  END FrameData_O[9]
  PIN FrameStrobe[0]
    DIRECTION INPUT ;
    USE SIGNAL ;
    ANTENNAGATEAREA 11.745500 ;
    PORT
      LAYER Metal2 ;
        RECT 204.760 0.000 205.160 0.400 ;
    END
  END FrameStrobe[0]
  PIN FrameStrobe[10]
    DIRECTION INPUT ;
    USE SIGNAL ;
    ANTENNAGATEAREA 11.745500 ;
    PORT
      LAYER Metal2 ;
        RECT 214.360 0.000 214.760 0.400 ;
    END
  END FrameStrobe[10]
  PIN FrameStrobe[11]
    DIRECTION INPUT ;
    USE SIGNAL ;
    ANTENNAGATEAREA 1.719900 ;
    PORT
      LAYER Metal2 ;
        RECT 215.320 0.000 215.720 0.400 ;
    END
  END FrameStrobe[11]
  PIN FrameStrobe[12]
    DIRECTION INPUT ;
    USE SIGNAL ;
    ANTENNAGATEAREA 1.719900 ;
    PORT
      LAYER Metal2 ;
        RECT 216.280 0.000 216.680 0.400 ;
    END
  END FrameStrobe[12]
  PIN FrameStrobe[13]
    DIRECTION INPUT ;
    USE SIGNAL ;
    ANTENNAGATEAREA 1.719900 ;
    PORT
      LAYER Metal2 ;
        RECT 217.240 0.000 217.640 0.400 ;
    END
  END FrameStrobe[13]
  PIN FrameStrobe[14]
    DIRECTION INPUT ;
    USE SIGNAL ;
    ANTENNAGATEAREA 1.142700 ;
    PORT
      LAYER Metal2 ;
        RECT 218.200 0.000 218.600 0.400 ;
    END
  END FrameStrobe[14]
  PIN FrameStrobe[15]
    DIRECTION INPUT ;
    USE SIGNAL ;
    ANTENNAGATEAREA 0.950300 ;
    PORT
      LAYER Metal2 ;
        RECT 219.160 0.000 219.560 0.400 ;
    END
  END FrameStrobe[15]
  PIN FrameStrobe[16]
    DIRECTION INPUT ;
    USE SIGNAL ;
    ANTENNAGATEAREA 0.950300 ;
    PORT
      LAYER Metal2 ;
        RECT 220.120 0.000 220.520 0.400 ;
    END
  END FrameStrobe[16]
  PIN FrameStrobe[17]
    DIRECTION INPUT ;
    USE SIGNAL ;
    ANTENNAGATEAREA 0.757900 ;
    PORT
      LAYER Metal2 ;
        RECT 221.080 0.000 221.480 0.400 ;
    END
  END FrameStrobe[17]
  PIN FrameStrobe[18]
    DIRECTION INPUT ;
    USE SIGNAL ;
    ANTENNAGATEAREA 0.757900 ;
    PORT
      LAYER Metal2 ;
        RECT 222.040 0.000 222.440 0.400 ;
    END
  END FrameStrobe[18]
  PIN FrameStrobe[19]
    DIRECTION INPUT ;
    USE SIGNAL ;
    ANTENNAGATEAREA 0.757900 ;
    PORT
      LAYER Metal2 ;
        RECT 223.000 0.000 223.400 0.400 ;
    END
  END FrameStrobe[19]
  PIN FrameStrobe[1]
    DIRECTION INPUT ;
    USE SIGNAL ;
    ANTENNAGATEAREA 11.745500 ;
    PORT
      LAYER Metal2 ;
        RECT 205.720 0.000 206.120 0.400 ;
    END
  END FrameStrobe[1]
  PIN FrameStrobe[2]
    DIRECTION INPUT ;
    USE SIGNAL ;
    ANTENNAGATEAREA 11.745500 ;
    PORT
      LAYER Metal2 ;
        RECT 206.680 0.000 207.080 0.400 ;
    END
  END FrameStrobe[2]
  PIN FrameStrobe[3]
    DIRECTION INPUT ;
    USE SIGNAL ;
    ANTENNAGATEAREA 11.745500 ;
    PORT
      LAYER Metal2 ;
        RECT 207.640 0.000 208.040 0.400 ;
    END
  END FrameStrobe[3]
  PIN FrameStrobe[4]
    DIRECTION INPUT ;
    USE SIGNAL ;
    ANTENNAGATEAREA 11.745500 ;
    PORT
      LAYER Metal2 ;
        RECT 208.600 0.000 209.000 0.400 ;
    END
  END FrameStrobe[4]
  PIN FrameStrobe[5]
    DIRECTION INPUT ;
    USE SIGNAL ;
    ANTENNAGATEAREA 11.745500 ;
    PORT
      LAYER Metal2 ;
        RECT 209.560 0.000 209.960 0.400 ;
    END
  END FrameStrobe[5]
  PIN FrameStrobe[6]
    DIRECTION INPUT ;
    USE SIGNAL ;
    ANTENNAGATEAREA 11.745500 ;
    PORT
      LAYER Metal2 ;
        RECT 210.520 0.000 210.920 0.400 ;
    END
  END FrameStrobe[6]
  PIN FrameStrobe[7]
    DIRECTION INPUT ;
    USE SIGNAL ;
    ANTENNAGATEAREA 11.745500 ;
    PORT
      LAYER Metal2 ;
        RECT 211.480 0.000 211.880 0.400 ;
    END
  END FrameStrobe[7]
  PIN FrameStrobe[8]
    DIRECTION INPUT ;
    USE SIGNAL ;
    ANTENNAGATEAREA 11.745500 ;
    PORT
      LAYER Metal2 ;
        RECT 212.440 0.000 212.840 0.400 ;
    END
  END FrameStrobe[8]
  PIN FrameStrobe[9]
    DIRECTION INPUT ;
    USE SIGNAL ;
    ANTENNAGATEAREA 11.745500 ;
    PORT
      LAYER Metal2 ;
        RECT 213.400 0.000 213.800 0.400 ;
    END
  END FrameStrobe[9]
  PIN FrameStrobe_O[0]
    DIRECTION OUTPUT ;
    USE SIGNAL ;
    ANTENNADIFFAREA 2.724000 ;
    PORT
      LAYER Metal2 ;
        RECT 204.760 271.760 205.160 272.160 ;
    END
  END FrameStrobe_O[0]
  PIN FrameStrobe_O[10]
    DIRECTION OUTPUT ;
    USE SIGNAL ;
    ANTENNADIFFAREA 2.724000 ;
    PORT
      LAYER Metal2 ;
        RECT 214.360 271.760 214.760 272.160 ;
    END
  END FrameStrobe_O[10]
  PIN FrameStrobe_O[11]
    DIRECTION OUTPUT ;
    USE SIGNAL ;
    ANTENNADIFFAREA 2.724000 ;
    PORT
      LAYER Metal2 ;
        RECT 215.320 271.760 215.720 272.160 ;
    END
  END FrameStrobe_O[11]
  PIN FrameStrobe_O[12]
    DIRECTION OUTPUT ;
    USE SIGNAL ;
    ANTENNADIFFAREA 2.724000 ;
    PORT
      LAYER Metal2 ;
        RECT 216.280 271.760 216.680 272.160 ;
    END
  END FrameStrobe_O[12]
  PIN FrameStrobe_O[13]
    DIRECTION OUTPUT ;
    USE SIGNAL ;
    ANTENNADIFFAREA 2.724000 ;
    PORT
      LAYER Metal2 ;
        RECT 217.240 271.760 217.640 272.160 ;
    END
  END FrameStrobe_O[13]
  PIN FrameStrobe_O[14]
    DIRECTION OUTPUT ;
    USE SIGNAL ;
    ANTENNADIFFAREA 2.724000 ;
    PORT
      LAYER Metal2 ;
        RECT 218.200 271.760 218.600 272.160 ;
    END
  END FrameStrobe_O[14]
  PIN FrameStrobe_O[15]
    DIRECTION OUTPUT ;
    USE SIGNAL ;
    ANTENNADIFFAREA 2.724000 ;
    PORT
      LAYER Metal2 ;
        RECT 219.160 271.760 219.560 272.160 ;
    END
  END FrameStrobe_O[15]
  PIN FrameStrobe_O[16]
    DIRECTION OUTPUT ;
    USE SIGNAL ;
    ANTENNADIFFAREA 2.724000 ;
    PORT
      LAYER Metal2 ;
        RECT 220.120 271.760 220.520 272.160 ;
    END
  END FrameStrobe_O[16]
  PIN FrameStrobe_O[17]
    DIRECTION OUTPUT ;
    USE SIGNAL ;
    ANTENNADIFFAREA 2.724000 ;
    PORT
      LAYER Metal2 ;
        RECT 221.080 271.760 221.480 272.160 ;
    END
  END FrameStrobe_O[17]
  PIN FrameStrobe_O[18]
    DIRECTION OUTPUT ;
    USE SIGNAL ;
    ANTENNADIFFAREA 2.724000 ;
    PORT
      LAYER Metal2 ;
        RECT 222.040 271.760 222.440 272.160 ;
    END
  END FrameStrobe_O[18]
  PIN FrameStrobe_O[19]
    DIRECTION OUTPUT ;
    USE SIGNAL ;
    ANTENNADIFFAREA 2.724000 ;
    PORT
      LAYER Metal2 ;
        RECT 223.000 271.760 223.400 272.160 ;
    END
  END FrameStrobe_O[19]
  PIN FrameStrobe_O[1]
    DIRECTION OUTPUT ;
    USE SIGNAL ;
    ANTENNADIFFAREA 2.724000 ;
    PORT
      LAYER Metal2 ;
        RECT 205.720 271.760 206.120 272.160 ;
    END
  END FrameStrobe_O[1]
  PIN FrameStrobe_O[2]
    DIRECTION OUTPUT ;
    USE SIGNAL ;
    ANTENNADIFFAREA 2.724000 ;
    PORT
      LAYER Metal2 ;
        RECT 206.680 271.760 207.080 272.160 ;
    END
  END FrameStrobe_O[2]
  PIN FrameStrobe_O[3]
    DIRECTION OUTPUT ;
    USE SIGNAL ;
    ANTENNADIFFAREA 2.724000 ;
    PORT
      LAYER Metal2 ;
        RECT 207.640 271.760 208.040 272.160 ;
    END
  END FrameStrobe_O[3]
  PIN FrameStrobe_O[4]
    DIRECTION OUTPUT ;
    USE SIGNAL ;
    ANTENNADIFFAREA 2.724000 ;
    PORT
      LAYER Metal2 ;
        RECT 208.600 271.760 209.000 272.160 ;
    END
  END FrameStrobe_O[4]
  PIN FrameStrobe_O[5]
    DIRECTION OUTPUT ;
    USE SIGNAL ;
    ANTENNADIFFAREA 2.724000 ;
    PORT
      LAYER Metal2 ;
        RECT 209.560 271.760 209.960 272.160 ;
    END
  END FrameStrobe_O[5]
  PIN FrameStrobe_O[6]
    DIRECTION OUTPUT ;
    USE SIGNAL ;
    ANTENNADIFFAREA 2.724000 ;
    PORT
      LAYER Metal2 ;
        RECT 210.520 271.760 210.920 272.160 ;
    END
  END FrameStrobe_O[6]
  PIN FrameStrobe_O[7]
    DIRECTION OUTPUT ;
    USE SIGNAL ;
    ANTENNADIFFAREA 2.724000 ;
    PORT
      LAYER Metal2 ;
        RECT 211.480 271.760 211.880 272.160 ;
    END
  END FrameStrobe_O[7]
  PIN FrameStrobe_O[8]
    DIRECTION OUTPUT ;
    USE SIGNAL ;
    ANTENNADIFFAREA 2.724000 ;
    PORT
      LAYER Metal2 ;
        RECT 212.440 271.760 212.840 272.160 ;
    END
  END FrameStrobe_O[8]
  PIN FrameStrobe_O[9]
    DIRECTION OUTPUT ;
    USE SIGNAL ;
    ANTENNADIFFAREA 2.724000 ;
    PORT
      LAYER Metal2 ;
        RECT 213.400 271.760 213.800 272.160 ;
    END
  END FrameStrobe_O[9]
  PIN N1BEG[0]
    DIRECTION OUTPUT ;
    USE SIGNAL ;
    ANTENNADIFFAREA 2.724000 ;
    PORT
      LAYER Metal2 ;
        RECT 1.240 271.760 1.640 272.160 ;
    END
  END N1BEG[0]
  PIN N1BEG[1]
    DIRECTION OUTPUT ;
    USE SIGNAL ;
    ANTENNADIFFAREA 2.724000 ;
    PORT
      LAYER Metal2 ;
        RECT 3.160 271.760 3.560 272.160 ;
    END
  END N1BEG[1]
  PIN N1BEG[2]
    DIRECTION OUTPUT ;
    USE SIGNAL ;
    ANTENNADIFFAREA 2.724000 ;
    PORT
      LAYER Metal2 ;
        RECT 5.080 271.760 5.480 272.160 ;
    END
  END N1BEG[2]
  PIN N1BEG[3]
    DIRECTION OUTPUT ;
    USE SIGNAL ;
    ANTENNADIFFAREA 2.724000 ;
    PORT
      LAYER Metal2 ;
        RECT 7.000 271.760 7.400 272.160 ;
    END
  END N1BEG[3]
  PIN N1END[0]
    DIRECTION INPUT ;
    USE SIGNAL ;
    ANTENNAGATEAREA 1.492400 ;
    PORT
      LAYER Metal2 ;
        RECT 1.240 0.000 1.640 0.400 ;
    END
  END N1END[0]
  PIN N1END[1]
    DIRECTION INPUT ;
    USE SIGNAL ;
    ANTENNAGATEAREA 1.918800 ;
    PORT
      LAYER Metal2 ;
        RECT 3.160 0.000 3.560 0.400 ;
    END
  END N1END[1]
  PIN N1END[2]
    DIRECTION INPUT ;
    USE SIGNAL ;
    ANTENNAGATEAREA 1.492400 ;
    PORT
      LAYER Metal2 ;
        RECT 5.080 0.000 5.480 0.400 ;
    END
  END N1END[2]
  PIN N1END[3]
    DIRECTION INPUT ;
    USE SIGNAL ;
    ANTENNAGATEAREA 1.492400 ;
    PORT
      LAYER Metal2 ;
        RECT 7.000 0.000 7.400 0.400 ;
    END
  END N1END[3]
  PIN N2BEG[0]
    DIRECTION OUTPUT ;
    USE SIGNAL ;
    ANTENNADIFFAREA 2.724000 ;
    PORT
      LAYER Metal2 ;
        RECT 11.800 271.760 12.200 272.160 ;
    END
  END N2BEG[0]
  PIN N2BEG[1]
    DIRECTION OUTPUT ;
    USE SIGNAL ;
    ANTENNADIFFAREA 2.724000 ;
    PORT
      LAYER Metal2 ;
        RECT 12.760 271.760 13.160 272.160 ;
    END
  END N2BEG[1]
  PIN N2BEG[2]
    DIRECTION OUTPUT ;
    USE SIGNAL ;
    ANTENNADIFFAREA 2.724000 ;
    PORT
      LAYER Metal2 ;
        RECT 13.720 271.760 14.120 272.160 ;
    END
  END N2BEG[2]
  PIN N2BEG[3]
    DIRECTION OUTPUT ;
    USE SIGNAL ;
    ANTENNADIFFAREA 2.724000 ;
    PORT
      LAYER Metal2 ;
        RECT 14.680 271.760 15.080 272.160 ;
    END
  END N2BEG[3]
  PIN N2BEG[4]
    DIRECTION OUTPUT ;
    USE SIGNAL ;
    ANTENNADIFFAREA 2.724000 ;
    PORT
      LAYER Metal2 ;
        RECT 15.640 271.760 16.040 272.160 ;
    END
  END N2BEG[4]
  PIN N2BEG[5]
    DIRECTION OUTPUT ;
    USE SIGNAL ;
    ANTENNADIFFAREA 2.724000 ;
    PORT
      LAYER Metal2 ;
        RECT 16.600 271.760 17.000 272.160 ;
    END
  END N2BEG[5]
  PIN N2BEG[6]
    DIRECTION OUTPUT ;
    USE SIGNAL ;
    ANTENNADIFFAREA 2.724000 ;
    PORT
      LAYER Metal2 ;
        RECT 17.560 271.760 17.960 272.160 ;
    END
  END N2BEG[6]
  PIN N2BEG[7]
    DIRECTION OUTPUT ;
    USE SIGNAL ;
    ANTENNADIFFAREA 2.724000 ;
    PORT
      LAYER Metal2 ;
        RECT 18.520 271.760 18.920 272.160 ;
    END
  END N2BEG[7]
  PIN N2BEGb[0]
    DIRECTION OUTPUT ;
    USE SIGNAL ;
    ANTENNADIFFAREA 2.724000 ;
    PORT
      LAYER Metal2 ;
        RECT 26.200 271.760 26.600 272.160 ;
    END
  END N2BEGb[0]
  PIN N2BEGb[1]
    DIRECTION OUTPUT ;
    USE SIGNAL ;
    ANTENNADIFFAREA 2.724000 ;
    PORT
      LAYER Metal2 ;
        RECT 27.160 271.760 27.560 272.160 ;
    END
  END N2BEGb[1]
  PIN N2BEGb[2]
    DIRECTION OUTPUT ;
    USE SIGNAL ;
    ANTENNADIFFAREA 2.724000 ;
    PORT
      LAYER Metal2 ;
        RECT 28.120 271.760 28.520 272.160 ;
    END
  END N2BEGb[2]
  PIN N2BEGb[3]
    DIRECTION OUTPUT ;
    USE SIGNAL ;
    ANTENNADIFFAREA 2.724000 ;
    PORT
      LAYER Metal2 ;
        RECT 29.080 271.760 29.480 272.160 ;
    END
  END N2BEGb[3]
  PIN N2BEGb[4]
    DIRECTION OUTPUT ;
    USE SIGNAL ;
    ANTENNADIFFAREA 2.724000 ;
    PORT
      LAYER Metal2 ;
        RECT 30.040 271.760 30.440 272.160 ;
    END
  END N2BEGb[4]
  PIN N2BEGb[5]
    DIRECTION OUTPUT ;
    USE SIGNAL ;
    ANTENNADIFFAREA 2.724000 ;
    PORT
      LAYER Metal2 ;
        RECT 31.000 271.760 31.400 272.160 ;
    END
  END N2BEGb[5]
  PIN N2BEGb[6]
    DIRECTION OUTPUT ;
    USE SIGNAL ;
    ANTENNADIFFAREA 2.724000 ;
    PORT
      LAYER Metal2 ;
        RECT 31.960 271.760 32.360 272.160 ;
    END
  END N2BEGb[6]
  PIN N2BEGb[7]
    DIRECTION OUTPUT ;
    USE SIGNAL ;
    ANTENNADIFFAREA 2.724000 ;
    PORT
      LAYER Metal2 ;
        RECT 32.920 271.760 33.320 272.160 ;
    END
  END N2BEGb[7]
  PIN N2END[0]
    DIRECTION INPUT ;
    USE SIGNAL ;
    ANTENNAGATEAREA 1.292200 ;
    PORT
      LAYER Metal2 ;
        RECT 26.200 0.000 26.600 0.400 ;
    END
  END N2END[0]
  PIN N2END[1]
    DIRECTION INPUT ;
    USE SIGNAL ;
    ANTENNAGATEAREA 1.505400 ;
    PORT
      LAYER Metal2 ;
        RECT 27.160 0.000 27.560 0.400 ;
    END
  END N2END[1]
  PIN N2END[2]
    DIRECTION INPUT ;
    USE SIGNAL ;
    ANTENNAGATEAREA 1.918800 ;
    PORT
      LAYER Metal2 ;
        RECT 28.120 0.000 28.520 0.400 ;
    END
  END N2END[2]
  PIN N2END[3]
    DIRECTION INPUT ;
    USE SIGNAL ;
    ANTENNAGATEAREA 1.918800 ;
    PORT
      LAYER Metal2 ;
        RECT 29.080 0.000 29.480 0.400 ;
    END
  END N2END[3]
  PIN N2END[4]
    DIRECTION INPUT ;
    USE SIGNAL ;
    ANTENNAGATEAREA 1.918800 ;
    PORT
      LAYER Metal2 ;
        RECT 30.040 0.000 30.440 0.400 ;
    END
  END N2END[4]
  PIN N2END[5]
    DIRECTION INPUT ;
    USE SIGNAL ;
    ANTENNAGATEAREA 1.492400 ;
    PORT
      LAYER Metal2 ;
        RECT 31.000 0.000 31.400 0.400 ;
    END
  END N2END[5]
  PIN N2END[6]
    DIRECTION INPUT ;
    USE SIGNAL ;
    ANTENNAGATEAREA 1.492400 ;
    PORT
      LAYER Metal2 ;
        RECT 31.960 0.000 32.360 0.400 ;
    END
  END N2END[6]
  PIN N2END[7]
    DIRECTION INPUT ;
    USE SIGNAL ;
    ANTENNAGATEAREA 1.492400 ;
    PORT
      LAYER Metal2 ;
        RECT 32.920 0.000 33.320 0.400 ;
    END
  END N2END[7]
  PIN N2MID[0]
    DIRECTION INPUT ;
    USE SIGNAL ;
    ANTENNAGATEAREA 2.325700 ;
    PORT
      LAYER Metal2 ;
        RECT 11.800 0.000 12.200 0.400 ;
    END
  END N2MID[0]
  PIN N2MID[1]
    DIRECTION INPUT ;
    USE SIGNAL ;
    ANTENNAGATEAREA 1.673100 ;
    PORT
      LAYER Metal2 ;
        RECT 12.760 0.000 13.160 0.400 ;
    END
  END N2MID[1]
  PIN N2MID[2]
    DIRECTION INPUT ;
    USE SIGNAL ;
    ANTENNAGATEAREA 1.246700 ;
    PORT
      LAYER Metal2 ;
        RECT 13.720 0.000 14.120 0.400 ;
    END
  END N2MID[2]
  PIN N2MID[3]
    DIRECTION INPUT ;
    USE SIGNAL ;
    ANTENNAGATEAREA 1.246700 ;
    PORT
      LAYER Metal2 ;
        RECT 14.680 0.000 15.080 0.400 ;
    END
  END N2MID[3]
  PIN N2MID[4]
    DIRECTION INPUT ;
    USE SIGNAL ;
    ANTENNAGATEAREA 1.459900 ;
    PORT
      LAYER Metal2 ;
        RECT 15.640 0.000 16.040 0.400 ;
    END
  END N2MID[4]
  PIN N2MID[5]
    DIRECTION INPUT ;
    USE SIGNAL ;
    ANTENNAGATEAREA 1.459900 ;
    PORT
      LAYER Metal2 ;
        RECT 16.600 0.000 17.000 0.400 ;
    END
  END N2MID[5]
  PIN N2MID[6]
    DIRECTION INPUT ;
    USE SIGNAL ;
    ANTENNAGATEAREA 1.246700 ;
    PORT
      LAYER Metal2 ;
        RECT 17.560 0.000 17.960 0.400 ;
    END
  END N2MID[6]
  PIN N2MID[7]
    DIRECTION INPUT ;
    USE SIGNAL ;
    ANTENNAGATEAREA 1.673100 ;
    PORT
      LAYER Metal2 ;
        RECT 18.520 0.000 18.920 0.400 ;
    END
  END N2MID[7]
  PIN N4BEG[0]
    DIRECTION OUTPUT ;
    USE SIGNAL ;
    ANTENNADIFFAREA 2.724000 ;
    PORT
      LAYER Metal2 ;
        RECT 44.440 271.760 44.840 272.160 ;
    END
  END N4BEG[0]
  PIN N4BEG[10]
    DIRECTION OUTPUT ;
    USE SIGNAL ;
    ANTENNADIFFAREA 2.724000 ;
    PORT
      LAYER Metal2 ;
        RECT 54.040 271.760 54.440 272.160 ;
    END
  END N4BEG[10]
  PIN N4BEG[11]
    DIRECTION OUTPUT ;
    USE SIGNAL ;
    ANTENNADIFFAREA 2.724000 ;
    PORT
      LAYER Metal2 ;
        RECT 55.000 271.760 55.400 272.160 ;
    END
  END N4BEG[11]
  PIN N4BEG[12]
    DIRECTION OUTPUT ;
    USE SIGNAL ;
    ANTENNADIFFAREA 2.724000 ;
    PORT
      LAYER Metal2 ;
        RECT 55.960 271.760 56.360 272.160 ;
    END
  END N4BEG[12]
  PIN N4BEG[13]
    DIRECTION OUTPUT ;
    USE SIGNAL ;
    ANTENNADIFFAREA 2.724000 ;
    PORT
      LAYER Metal2 ;
        RECT 56.920 271.760 57.320 272.160 ;
    END
  END N4BEG[13]
  PIN N4BEG[14]
    DIRECTION OUTPUT ;
    USE SIGNAL ;
    ANTENNADIFFAREA 2.724000 ;
    PORT
      LAYER Metal2 ;
        RECT 57.880 271.760 58.280 272.160 ;
    END
  END N4BEG[14]
  PIN N4BEG[15]
    DIRECTION OUTPUT ;
    USE SIGNAL ;
    ANTENNADIFFAREA 2.724000 ;
    PORT
      LAYER Metal2 ;
        RECT 58.840 271.760 59.240 272.160 ;
    END
  END N4BEG[15]
  PIN N4BEG[1]
    DIRECTION OUTPUT ;
    USE SIGNAL ;
    ANTENNADIFFAREA 2.724000 ;
    PORT
      LAYER Metal2 ;
        RECT 45.400 271.760 45.800 272.160 ;
    END
  END N4BEG[1]
  PIN N4BEG[2]
    DIRECTION OUTPUT ;
    USE SIGNAL ;
    ANTENNADIFFAREA 2.724000 ;
    PORT
      LAYER Metal2 ;
        RECT 46.360 271.760 46.760 272.160 ;
    END
  END N4BEG[2]
  PIN N4BEG[3]
    DIRECTION OUTPUT ;
    USE SIGNAL ;
    ANTENNADIFFAREA 2.724000 ;
    PORT
      LAYER Metal2 ;
        RECT 47.320 271.760 47.720 272.160 ;
    END
  END N4BEG[3]
  PIN N4BEG[4]
    DIRECTION OUTPUT ;
    USE SIGNAL ;
    ANTENNADIFFAREA 2.724000 ;
    PORT
      LAYER Metal2 ;
        RECT 48.280 271.760 48.680 272.160 ;
    END
  END N4BEG[4]
  PIN N4BEG[5]
    DIRECTION OUTPUT ;
    USE SIGNAL ;
    ANTENNADIFFAREA 2.724000 ;
    PORT
      LAYER Metal2 ;
        RECT 49.240 271.760 49.640 272.160 ;
    END
  END N4BEG[5]
  PIN N4BEG[6]
    DIRECTION OUTPUT ;
    USE SIGNAL ;
    ANTENNADIFFAREA 2.724000 ;
    PORT
      LAYER Metal2 ;
        RECT 50.200 271.760 50.600 272.160 ;
    END
  END N4BEG[6]
  PIN N4BEG[7]
    DIRECTION OUTPUT ;
    USE SIGNAL ;
    ANTENNADIFFAREA 2.724000 ;
    PORT
      LAYER Metal2 ;
        RECT 51.160 271.760 51.560 272.160 ;
    END
  END N4BEG[7]
  PIN N4BEG[8]
    DIRECTION OUTPUT ;
    USE SIGNAL ;
    ANTENNADIFFAREA 2.724000 ;
    PORT
      LAYER Metal2 ;
        RECT 52.120 271.760 52.520 272.160 ;
    END
  END N4BEG[8]
  PIN N4BEG[9]
    DIRECTION OUTPUT ;
    USE SIGNAL ;
    ANTENNADIFFAREA 2.724000 ;
    PORT
      LAYER Metal2 ;
        RECT 53.080 271.760 53.480 272.160 ;
    END
  END N4BEG[9]
  PIN N4END[0]
    DIRECTION INPUT ;
    USE SIGNAL ;
    ANTENNAGATEAREA 1.718600 ;
    PORT
      LAYER Metal2 ;
        RECT 44.440 0.000 44.840 0.400 ;
    END
  END N4END[0]
  PIN N4END[10]
    DIRECTION INPUT ;
    USE SIGNAL ;
    ANTENNAGATEAREA 0.180700 ;
    PORT
      LAYER Metal2 ;
        RECT 54.040 0.000 54.440 0.400 ;
    END
  END N4END[10]
  PIN N4END[11]
    DIRECTION INPUT ;
    USE SIGNAL ;
    ANTENNAGATEAREA 0.180700 ;
    PORT
      LAYER Metal2 ;
        RECT 55.000 0.000 55.400 0.400 ;
    END
  END N4END[11]
  PIN N4END[12]
    DIRECTION INPUT ;
    USE SIGNAL ;
    ANTENNAGATEAREA 0.180700 ;
    PORT
      LAYER Metal2 ;
        RECT 55.960 0.000 56.360 0.400 ;
    END
  END N4END[12]
  PIN N4END[13]
    DIRECTION INPUT ;
    USE SIGNAL ;
    ANTENNAGATEAREA 0.180700 ;
    PORT
      LAYER Metal2 ;
        RECT 56.920 0.000 57.320 0.400 ;
    END
  END N4END[13]
  PIN N4END[14]
    DIRECTION INPUT ;
    USE SIGNAL ;
    ANTENNAGATEAREA 0.180700 ;
    PORT
      LAYER Metal2 ;
        RECT 57.880 0.000 58.280 0.400 ;
    END
  END N4END[14]
  PIN N4END[15]
    DIRECTION INPUT ;
    USE SIGNAL ;
    ANTENNAGATEAREA 0.180700 ;
    PORT
      LAYER Metal2 ;
        RECT 58.840 0.000 59.240 0.400 ;
    END
  END N4END[15]
  PIN N4END[1]
    DIRECTION INPUT ;
    USE SIGNAL ;
    ANTENNAGATEAREA 1.718600 ;
    PORT
      LAYER Metal2 ;
        RECT 45.400 0.000 45.800 0.400 ;
    END
  END N4END[1]
  PIN N4END[2]
    DIRECTION INPUT ;
    USE SIGNAL ;
    ANTENNAGATEAREA 1.705600 ;
    PORT
      LAYER Metal2 ;
        RECT 46.360 0.000 46.760 0.400 ;
    END
  END N4END[2]
  PIN N4END[3]
    DIRECTION INPUT ;
    USE SIGNAL ;
    ANTENNAGATEAREA 1.492400 ;
    PORT
      LAYER Metal2 ;
        RECT 47.320 0.000 47.720 0.400 ;
    END
  END N4END[3]
  PIN N4END[4]
    DIRECTION INPUT ;
    USE SIGNAL ;
    ANTENNAGATEAREA 0.180700 ;
    PORT
      LAYER Metal2 ;
        RECT 48.280 0.000 48.680 0.400 ;
    END
  END N4END[4]
  PIN N4END[5]
    DIRECTION INPUT ;
    USE SIGNAL ;
    ANTENNAGATEAREA 0.180700 ;
    PORT
      LAYER Metal2 ;
        RECT 49.240 0.000 49.640 0.400 ;
    END
  END N4END[5]
  PIN N4END[6]
    DIRECTION INPUT ;
    USE SIGNAL ;
    ANTENNAGATEAREA 0.180700 ;
    PORT
      LAYER Metal2 ;
        RECT 50.200 0.000 50.600 0.400 ;
    END
  END N4END[6]
  PIN N4END[7]
    DIRECTION INPUT ;
    USE SIGNAL ;
    ANTENNAGATEAREA 0.180700 ;
    PORT
      LAYER Metal2 ;
        RECT 51.160 0.000 51.560 0.400 ;
    END
  END N4END[7]
  PIN N4END[8]
    DIRECTION INPUT ;
    USE SIGNAL ;
    ANTENNAGATEAREA 0.180700 ;
    PORT
      LAYER Metal2 ;
        RECT 52.120 0.000 52.520 0.400 ;
    END
  END N4END[8]
  PIN N4END[9]
    DIRECTION INPUT ;
    USE SIGNAL ;
    ANTENNAGATEAREA 0.180700 ;
    PORT
      LAYER Metal2 ;
        RECT 53.080 0.000 53.480 0.400 ;
    END
  END N4END[9]
  PIN NN4BEG[0]
    DIRECTION OUTPUT ;
    USE SIGNAL ;
    ANTENNADIFFAREA 2.724000 ;
    PORT
      LAYER Metal2 ;
        RECT 74.200 271.760 74.600 272.160 ;
    END
  END NN4BEG[0]
  PIN NN4BEG[10]
    DIRECTION OUTPUT ;
    USE SIGNAL ;
    ANTENNADIFFAREA 2.724000 ;
    PORT
      LAYER Metal2 ;
        RECT 83.800 271.760 84.200 272.160 ;
    END
  END NN4BEG[10]
  PIN NN4BEG[11]
    DIRECTION OUTPUT ;
    USE SIGNAL ;
    ANTENNADIFFAREA 2.724000 ;
    PORT
      LAYER Metal2 ;
        RECT 84.760 271.760 85.160 272.160 ;
    END
  END NN4BEG[11]
  PIN NN4BEG[12]
    DIRECTION OUTPUT ;
    USE SIGNAL ;
    ANTENNADIFFAREA 2.724000 ;
    PORT
      LAYER Metal2 ;
        RECT 85.720 271.760 86.120 272.160 ;
    END
  END NN4BEG[12]
  PIN NN4BEG[13]
    DIRECTION OUTPUT ;
    USE SIGNAL ;
    ANTENNADIFFAREA 2.724000 ;
    PORT
      LAYER Metal2 ;
        RECT 86.680 271.760 87.080 272.160 ;
    END
  END NN4BEG[13]
  PIN NN4BEG[14]
    DIRECTION OUTPUT ;
    USE SIGNAL ;
    ANTENNADIFFAREA 2.724000 ;
    PORT
      LAYER Metal2 ;
        RECT 87.640 271.760 88.040 272.160 ;
    END
  END NN4BEG[14]
  PIN NN4BEG[15]
    DIRECTION OUTPUT ;
    USE SIGNAL ;
    ANTENNADIFFAREA 2.724000 ;
    PORT
      LAYER Metal2 ;
        RECT 88.600 271.760 89.000 272.160 ;
    END
  END NN4BEG[15]
  PIN NN4BEG[1]
    DIRECTION OUTPUT ;
    USE SIGNAL ;
    ANTENNADIFFAREA 2.724000 ;
    PORT
      LAYER Metal2 ;
        RECT 75.160 271.760 75.560 272.160 ;
    END
  END NN4BEG[1]
  PIN NN4BEG[2]
    DIRECTION OUTPUT ;
    USE SIGNAL ;
    ANTENNADIFFAREA 2.724000 ;
    PORT
      LAYER Metal2 ;
        RECT 76.120 271.760 76.520 272.160 ;
    END
  END NN4BEG[2]
  PIN NN4BEG[3]
    DIRECTION OUTPUT ;
    USE SIGNAL ;
    ANTENNADIFFAREA 2.724000 ;
    PORT
      LAYER Metal2 ;
        RECT 77.080 271.760 77.480 272.160 ;
    END
  END NN4BEG[3]
  PIN NN4BEG[4]
    DIRECTION OUTPUT ;
    USE SIGNAL ;
    ANTENNADIFFAREA 2.724000 ;
    PORT
      LAYER Metal2 ;
        RECT 78.040 271.760 78.440 272.160 ;
    END
  END NN4BEG[4]
  PIN NN4BEG[5]
    DIRECTION OUTPUT ;
    USE SIGNAL ;
    ANTENNADIFFAREA 2.724000 ;
    PORT
      LAYER Metal2 ;
        RECT 79.000 271.760 79.400 272.160 ;
    END
  END NN4BEG[5]
  PIN NN4BEG[6]
    DIRECTION OUTPUT ;
    USE SIGNAL ;
    ANTENNADIFFAREA 2.724000 ;
    PORT
      LAYER Metal2 ;
        RECT 79.960 271.760 80.360 272.160 ;
    END
  END NN4BEG[6]
  PIN NN4BEG[7]
    DIRECTION OUTPUT ;
    USE SIGNAL ;
    ANTENNADIFFAREA 2.724000 ;
    PORT
      LAYER Metal2 ;
        RECT 80.920 271.760 81.320 272.160 ;
    END
  END NN4BEG[7]
  PIN NN4BEG[8]
    DIRECTION OUTPUT ;
    USE SIGNAL ;
    ANTENNADIFFAREA 2.724000 ;
    PORT
      LAYER Metal2 ;
        RECT 81.880 271.760 82.280 272.160 ;
    END
  END NN4BEG[8]
  PIN NN4BEG[9]
    DIRECTION OUTPUT ;
    USE SIGNAL ;
    ANTENNADIFFAREA 2.724000 ;
    PORT
      LAYER Metal2 ;
        RECT 82.840 271.760 83.240 272.160 ;
    END
  END NN4BEG[9]
  PIN NN4END[0]
    DIRECTION INPUT ;
    USE SIGNAL ;
    ANTENNAGATEAREA 1.918800 ;
    PORT
      LAYER Metal2 ;
        RECT 74.200 0.000 74.600 0.400 ;
    END
  END NN4END[0]
  PIN NN4END[10]
    DIRECTION INPUT ;
    USE SIGNAL ;
    ANTENNAGATEAREA 0.180700 ;
    PORT
      LAYER Metal2 ;
        RECT 83.800 0.000 84.200 0.400 ;
    END
  END NN4END[10]
  PIN NN4END[11]
    DIRECTION INPUT ;
    USE SIGNAL ;
    ANTENNAGATEAREA 0.180700 ;
    PORT
      LAYER Metal2 ;
        RECT 84.760 0.000 85.160 0.400 ;
    END
  END NN4END[11]
  PIN NN4END[12]
    DIRECTION INPUT ;
    USE SIGNAL ;
    ANTENNAGATEAREA 0.180700 ;
    PORT
      LAYER Metal2 ;
        RECT 85.720 0.000 86.120 0.400 ;
    END
  END NN4END[12]
  PIN NN4END[13]
    DIRECTION INPUT ;
    USE SIGNAL ;
    ANTENNAGATEAREA 0.180700 ;
    PORT
      LAYER Metal2 ;
        RECT 86.680 0.000 87.080 0.400 ;
    END
  END NN4END[13]
  PIN NN4END[14]
    DIRECTION INPUT ;
    USE SIGNAL ;
    ANTENNAGATEAREA 0.180700 ;
    PORT
      LAYER Metal2 ;
        RECT 87.640 0.000 88.040 0.400 ;
    END
  END NN4END[14]
  PIN NN4END[15]
    DIRECTION INPUT ;
    USE SIGNAL ;
    ANTENNAGATEAREA 0.180700 ;
    PORT
      LAYER Metal2 ;
        RECT 88.600 0.000 89.000 0.400 ;
    END
  END NN4END[15]
  PIN NN4END[1]
    DIRECTION INPUT ;
    USE SIGNAL ;
    ANTENNAGATEAREA 1.705600 ;
    PORT
      LAYER Metal2 ;
        RECT 75.160 0.000 75.560 0.400 ;
    END
  END NN4END[1]
  PIN NN4END[2]
    DIRECTION INPUT ;
    USE SIGNAL ;
    ANTENNAGATEAREA 2.132000 ;
    PORT
      LAYER Metal2 ;
        RECT 76.120 0.000 76.520 0.400 ;
    END
  END NN4END[2]
  PIN NN4END[3]
    DIRECTION INPUT ;
    USE SIGNAL ;
    ANTENNAGATEAREA 1.492400 ;
    PORT
      LAYER Metal2 ;
        RECT 77.080 0.000 77.480 0.400 ;
    END
  END NN4END[3]
  PIN NN4END[4]
    DIRECTION INPUT ;
    USE SIGNAL ;
    ANTENNAGATEAREA 0.180700 ;
    PORT
      LAYER Metal2 ;
        RECT 78.040 0.000 78.440 0.400 ;
    END
  END NN4END[4]
  PIN NN4END[5]
    DIRECTION INPUT ;
    USE SIGNAL ;
    ANTENNAGATEAREA 0.180700 ;
    PORT
      LAYER Metal2 ;
        RECT 79.000 0.000 79.400 0.400 ;
    END
  END NN4END[5]
  PIN NN4END[6]
    DIRECTION INPUT ;
    USE SIGNAL ;
    ANTENNAGATEAREA 0.180700 ;
    PORT
      LAYER Metal2 ;
        RECT 79.960 0.000 80.360 0.400 ;
    END
  END NN4END[6]
  PIN NN4END[7]
    DIRECTION INPUT ;
    USE SIGNAL ;
    ANTENNAGATEAREA 0.180700 ;
    PORT
      LAYER Metal2 ;
        RECT 80.920 0.000 81.320 0.400 ;
    END
  END NN4END[7]
  PIN NN4END[8]
    DIRECTION INPUT ;
    USE SIGNAL ;
    ANTENNAGATEAREA 0.180700 ;
    PORT
      LAYER Metal2 ;
        RECT 81.880 0.000 82.280 0.400 ;
    END
  END NN4END[8]
  PIN NN4END[9]
    DIRECTION INPUT ;
    USE SIGNAL ;
    ANTENNAGATEAREA 0.180700 ;
    PORT
      LAYER Metal2 ;
        RECT 82.840 0.000 83.240 0.400 ;
    END
  END NN4END[9]
  PIN S1BEG[0]
    DIRECTION OUTPUT ;
    USE SIGNAL ;
    ANTENNADIFFAREA 2.724000 ;
    PORT
      LAYER Metal2 ;
        RECT 97.240 0.000 97.640 0.400 ;
    END
  END S1BEG[0]
  PIN S1BEG[1]
    DIRECTION OUTPUT ;
    USE SIGNAL ;
    ANTENNADIFFAREA 2.724000 ;
    PORT
      LAYER Metal2 ;
        RECT 99.160 0.000 99.560 0.400 ;
    END
  END S1BEG[1]
  PIN S1BEG[2]
    DIRECTION OUTPUT ;
    USE SIGNAL ;
    ANTENNADIFFAREA 2.724000 ;
    PORT
      LAYER Metal2 ;
        RECT 101.080 0.000 101.480 0.400 ;
    END
  END S1BEG[2]
  PIN S1BEG[3]
    DIRECTION OUTPUT ;
    USE SIGNAL ;
    ANTENNADIFFAREA 2.724000 ;
    PORT
      LAYER Metal2 ;
        RECT 103.000 0.000 103.400 0.400 ;
    END
  END S1BEG[3]
  PIN S1END[0]
    DIRECTION INPUT ;
    USE SIGNAL ;
    ANTENNAGATEAREA 1.492400 ;
    PORT
      LAYER Metal2 ;
        RECT 97.240 271.760 97.640 272.160 ;
    END
  END S1END[0]
  PIN S1END[1]
    DIRECTION INPUT ;
    USE SIGNAL ;
    ANTENNAGATEAREA 1.705600 ;
    PORT
      LAYER Metal2 ;
        RECT 99.160 271.760 99.560 272.160 ;
    END
  END S1END[1]
  PIN S1END[2]
    DIRECTION INPUT ;
    USE SIGNAL ;
    ANTENNAGATEAREA 1.705600 ;
    PORT
      LAYER Metal2 ;
        RECT 101.080 271.760 101.480 272.160 ;
    END
  END S1END[2]
  PIN S1END[3]
    DIRECTION INPUT ;
    USE SIGNAL ;
    ANTENNAGATEAREA 1.279200 ;
    PORT
      LAYER Metal2 ;
        RECT 103.000 271.760 103.400 272.160 ;
    END
  END S1END[3]
  PIN S2BEG[0]
    DIRECTION OUTPUT ;
    USE SIGNAL ;
    ANTENNADIFFAREA 2.724000 ;
    PORT
      LAYER Metal2 ;
        RECT 104.920 0.000 105.320 0.400 ;
    END
  END S2BEG[0]
  PIN S2BEG[1]
    DIRECTION OUTPUT ;
    USE SIGNAL ;
    ANTENNADIFFAREA 2.724000 ;
    PORT
      LAYER Metal2 ;
        RECT 106.840 0.000 107.240 0.400 ;
    END
  END S2BEG[1]
  PIN S2BEG[2]
    DIRECTION OUTPUT ;
    USE SIGNAL ;
    ANTENNADIFFAREA 2.724000 ;
    PORT
      LAYER Metal2 ;
        RECT 108.760 0.000 109.160 0.400 ;
    END
  END S2BEG[2]
  PIN S2BEG[3]
    DIRECTION OUTPUT ;
    USE SIGNAL ;
    ANTENNADIFFAREA 2.724000 ;
    PORT
      LAYER Metal2 ;
        RECT 110.680 0.000 111.080 0.400 ;
    END
  END S2BEG[3]
  PIN S2BEG[4]
    DIRECTION OUTPUT ;
    USE SIGNAL ;
    ANTENNADIFFAREA 2.724000 ;
    PORT
      LAYER Metal2 ;
        RECT 112.600 0.000 113.000 0.400 ;
    END
  END S2BEG[4]
  PIN S2BEG[5]
    DIRECTION OUTPUT ;
    USE SIGNAL ;
    ANTENNADIFFAREA 2.724000 ;
    PORT
      LAYER Metal2 ;
        RECT 114.520 0.000 114.920 0.400 ;
    END
  END S2BEG[5]
  PIN S2BEG[6]
    DIRECTION OUTPUT ;
    USE SIGNAL ;
    ANTENNADIFFAREA 2.724000 ;
    PORT
      LAYER Metal2 ;
        RECT 116.440 0.000 116.840 0.400 ;
    END
  END S2BEG[6]
  PIN S2BEG[7]
    DIRECTION OUTPUT ;
    USE SIGNAL ;
    ANTENNADIFFAREA 2.724000 ;
    PORT
      LAYER Metal2 ;
        RECT 118.360 0.000 118.760 0.400 ;
    END
  END S2BEG[7]
  PIN S2BEGb[0]
    DIRECTION OUTPUT ;
    USE SIGNAL ;
    ANTENNADIFFAREA 2.724000 ;
    PORT
      LAYER Metal2 ;
        RECT 123.160 0.000 123.560 0.400 ;
    END
  END S2BEGb[0]
  PIN S2BEGb[1]
    DIRECTION OUTPUT ;
    USE SIGNAL ;
    ANTENNADIFFAREA 2.724000 ;
    PORT
      LAYER Metal2 ;
        RECT 124.120 0.000 124.520 0.400 ;
    END
  END S2BEGb[1]
  PIN S2BEGb[2]
    DIRECTION OUTPUT ;
    USE SIGNAL ;
    ANTENNADIFFAREA 2.724000 ;
    PORT
      LAYER Metal2 ;
        RECT 125.080 0.000 125.480 0.400 ;
    END
  END S2BEGb[2]
  PIN S2BEGb[3]
    DIRECTION OUTPUT ;
    USE SIGNAL ;
    ANTENNADIFFAREA 2.724000 ;
    PORT
      LAYER Metal2 ;
        RECT 126.040 0.000 126.440 0.400 ;
    END
  END S2BEGb[3]
  PIN S2BEGb[4]
    DIRECTION OUTPUT ;
    USE SIGNAL ;
    ANTENNADIFFAREA 2.724000 ;
    PORT
      LAYER Metal2 ;
        RECT 127.000 0.000 127.400 0.400 ;
    END
  END S2BEGb[4]
  PIN S2BEGb[5]
    DIRECTION OUTPUT ;
    USE SIGNAL ;
    ANTENNADIFFAREA 2.724000 ;
    PORT
      LAYER Metal2 ;
        RECT 127.960 0.000 128.360 0.400 ;
    END
  END S2BEGb[5]
  PIN S2BEGb[6]
    DIRECTION OUTPUT ;
    USE SIGNAL ;
    ANTENNADIFFAREA 2.724000 ;
    PORT
      LAYER Metal2 ;
        RECT 128.920 0.000 129.320 0.400 ;
    END
  END S2BEGb[6]
  PIN S2BEGb[7]
    DIRECTION OUTPUT ;
    USE SIGNAL ;
    ANTENNADIFFAREA 2.724000 ;
    PORT
      LAYER Metal2 ;
        RECT 129.880 0.000 130.280 0.400 ;
    END
  END S2BEGb[7]
  PIN S2END[0]
    DIRECTION INPUT ;
    USE SIGNAL ;
    ANTENNAGATEAREA 1.066000 ;
    PORT
      LAYER Metal2 ;
        RECT 123.160 271.760 123.560 272.160 ;
    END
  END S2END[0]
  PIN S2END[1]
    DIRECTION INPUT ;
    USE SIGNAL ;
    ANTENNAGATEAREA 1.279200 ;
    PORT
      LAYER Metal2 ;
        RECT 124.120 271.760 124.520 272.160 ;
    END
  END S2END[1]
  PIN S2END[2]
    DIRECTION INPUT ;
    USE SIGNAL ;
    ANTENNAGATEAREA 1.705600 ;
    PORT
      LAYER Metal2 ;
        RECT 125.080 271.760 125.480 272.160 ;
    END
  END S2END[2]
  PIN S2END[3]
    DIRECTION INPUT ;
    USE SIGNAL ;
    ANTENNAGATEAREA 1.918800 ;
    PORT
      LAYER Metal2 ;
        RECT 126.040 271.760 126.440 272.160 ;
    END
  END S2END[3]
  PIN S2END[4]
    DIRECTION INPUT ;
    USE SIGNAL ;
    ANTENNAGATEAREA 1.492400 ;
    PORT
      LAYER Metal2 ;
        RECT 127.000 271.760 127.400 272.160 ;
    END
  END S2END[4]
  PIN S2END[5]
    DIRECTION INPUT ;
    USE SIGNAL ;
    ANTENNAGATEAREA 1.292200 ;
    PORT
      LAYER Metal2 ;
        RECT 127.960 271.760 128.360 272.160 ;
    END
  END S2END[5]
  PIN S2END[6]
    DIRECTION INPUT ;
    USE SIGNAL ;
    ANTENNAGATEAREA 1.492400 ;
    PORT
      LAYER Metal2 ;
        RECT 128.920 271.760 129.320 272.160 ;
    END
  END S2END[6]
  PIN S2END[7]
    DIRECTION INPUT ;
    USE SIGNAL ;
    ANTENNAGATEAREA 1.492400 ;
    PORT
      LAYER Metal2 ;
        RECT 129.880 271.760 130.280 272.160 ;
    END
  END S2END[7]
  PIN S2MID[0]
    DIRECTION INPUT ;
    USE SIGNAL ;
    ANTENNAGATEAREA 1.886300 ;
    PORT
      LAYER Metal2 ;
        RECT 104.920 271.760 105.320 272.160 ;
    END
  END S2MID[0]
  PIN S2MID[1]
    DIRECTION INPUT ;
    USE SIGNAL ;
    ANTENNAGATEAREA 1.459900 ;
    PORT
      LAYER Metal2 ;
        RECT 106.840 271.760 107.240 272.160 ;
    END
  END S2MID[1]
  PIN S2MID[2]
    DIRECTION INPUT ;
    USE SIGNAL ;
    ANTENNAGATEAREA 1.459900 ;
    PORT
      LAYER Metal2 ;
        RECT 108.760 271.760 109.160 272.160 ;
    END
  END S2MID[2]
  PIN S2MID[3]
    DIRECTION INPUT ;
    USE SIGNAL ;
    ANTENNAGATEAREA 1.246700 ;
    PORT
      LAYER Metal2 ;
        RECT 110.680 271.760 111.080 272.160 ;
    END
  END S2MID[3]
  PIN S2MID[4]
    DIRECTION INPUT ;
    USE SIGNAL ;
    ANTENNAGATEAREA 1.472900 ;
    PORT
      LAYER Metal2 ;
        RECT 112.600 271.760 113.000 272.160 ;
    END
  END S2MID[4]
  PIN S2MID[5]
    DIRECTION INPUT ;
    USE SIGNAL ;
    ANTENNAGATEAREA 1.673100 ;
    PORT
      LAYER Metal2 ;
        RECT 114.520 271.760 114.920 272.160 ;
    END
  END S2MID[5]
  PIN S2MID[6]
    DIRECTION INPUT ;
    USE SIGNAL ;
    ANTENNAGATEAREA 1.459900 ;
    PORT
      LAYER Metal2 ;
        RECT 116.440 271.760 116.840 272.160 ;
    END
  END S2MID[6]
  PIN S2MID[7]
    DIRECTION INPUT ;
    USE SIGNAL ;
    ANTENNAGATEAREA 1.673100 ;
    PORT
      LAYER Metal2 ;
        RECT 118.360 271.760 118.760 272.160 ;
    END
  END S2MID[7]
  PIN S4BEG[0]
    DIRECTION OUTPUT ;
    USE SIGNAL ;
    ANTENNADIFFAREA 2.724000 ;
    PORT
      LAYER Metal2 ;
        RECT 141.400 0.000 141.800 0.400 ;
    END
  END S4BEG[0]
  PIN S4BEG[10]
    DIRECTION OUTPUT ;
    USE SIGNAL ;
    ANTENNADIFFAREA 2.724000 ;
    PORT
      LAYER Metal2 ;
        RECT 151.000 0.000 151.400 0.400 ;
    END
  END S4BEG[10]
  PIN S4BEG[11]
    DIRECTION OUTPUT ;
    USE SIGNAL ;
    ANTENNADIFFAREA 2.724000 ;
    PORT
      LAYER Metal2 ;
        RECT 151.960 0.000 152.360 0.400 ;
    END
  END S4BEG[11]
  PIN S4BEG[12]
    DIRECTION OUTPUT ;
    USE SIGNAL ;
    ANTENNADIFFAREA 2.724000 ;
    PORT
      LAYER Metal2 ;
        RECT 152.920 0.000 153.320 0.400 ;
    END
  END S4BEG[12]
  PIN S4BEG[13]
    DIRECTION OUTPUT ;
    USE SIGNAL ;
    ANTENNADIFFAREA 2.724000 ;
    PORT
      LAYER Metal2 ;
        RECT 153.880 0.000 154.280 0.400 ;
    END
  END S4BEG[13]
  PIN S4BEG[14]
    DIRECTION OUTPUT ;
    USE SIGNAL ;
    ANTENNADIFFAREA 2.724000 ;
    PORT
      LAYER Metal2 ;
        RECT 154.840 0.000 155.240 0.400 ;
    END
  END S4BEG[14]
  PIN S4BEG[15]
    DIRECTION OUTPUT ;
    USE SIGNAL ;
    ANTENNADIFFAREA 2.724000 ;
    PORT
      LAYER Metal2 ;
        RECT 155.800 0.000 156.200 0.400 ;
    END
  END S4BEG[15]
  PIN S4BEG[1]
    DIRECTION OUTPUT ;
    USE SIGNAL ;
    ANTENNADIFFAREA 2.724000 ;
    PORT
      LAYER Metal2 ;
        RECT 142.360 0.000 142.760 0.400 ;
    END
  END S4BEG[1]
  PIN S4BEG[2]
    DIRECTION OUTPUT ;
    USE SIGNAL ;
    ANTENNADIFFAREA 2.724000 ;
    PORT
      LAYER Metal2 ;
        RECT 143.320 0.000 143.720 0.400 ;
    END
  END S4BEG[2]
  PIN S4BEG[3]
    DIRECTION OUTPUT ;
    USE SIGNAL ;
    ANTENNADIFFAREA 2.724000 ;
    PORT
      LAYER Metal2 ;
        RECT 144.280 0.000 144.680 0.400 ;
    END
  END S4BEG[3]
  PIN S4BEG[4]
    DIRECTION OUTPUT ;
    USE SIGNAL ;
    ANTENNADIFFAREA 2.724000 ;
    PORT
      LAYER Metal2 ;
        RECT 145.240 0.000 145.640 0.400 ;
    END
  END S4BEG[4]
  PIN S4BEG[5]
    DIRECTION OUTPUT ;
    USE SIGNAL ;
    ANTENNADIFFAREA 2.724000 ;
    PORT
      LAYER Metal2 ;
        RECT 146.200 0.000 146.600 0.400 ;
    END
  END S4BEG[5]
  PIN S4BEG[6]
    DIRECTION OUTPUT ;
    USE SIGNAL ;
    ANTENNADIFFAREA 2.724000 ;
    PORT
      LAYER Metal2 ;
        RECT 147.160 0.000 147.560 0.400 ;
    END
  END S4BEG[6]
  PIN S4BEG[7]
    DIRECTION OUTPUT ;
    USE SIGNAL ;
    ANTENNADIFFAREA 2.724000 ;
    PORT
      LAYER Metal2 ;
        RECT 148.120 0.000 148.520 0.400 ;
    END
  END S4BEG[7]
  PIN S4BEG[8]
    DIRECTION OUTPUT ;
    USE SIGNAL ;
    ANTENNADIFFAREA 2.724000 ;
    PORT
      LAYER Metal2 ;
        RECT 149.080 0.000 149.480 0.400 ;
    END
  END S4BEG[8]
  PIN S4BEG[9]
    DIRECTION OUTPUT ;
    USE SIGNAL ;
    ANTENNADIFFAREA 2.724000 ;
    PORT
      LAYER Metal2 ;
        RECT 150.040 0.000 150.440 0.400 ;
    END
  END S4BEG[9]
  PIN S4END[0]
    DIRECTION INPUT ;
    USE SIGNAL ;
    ANTENNAGATEAREA 1.705600 ;
    PORT
      LAYER Metal2 ;
        RECT 141.400 271.760 141.800 272.160 ;
    END
  END S4END[0]
  PIN S4END[10]
    DIRECTION INPUT ;
    USE SIGNAL ;
    ANTENNAGATEAREA 0.180700 ;
    PORT
      LAYER Metal2 ;
        RECT 151.000 271.760 151.400 272.160 ;
    END
  END S4END[10]
  PIN S4END[11]
    DIRECTION INPUT ;
    USE SIGNAL ;
    ANTENNAGATEAREA 0.180700 ;
    PORT
      LAYER Metal2 ;
        RECT 151.960 271.760 152.360 272.160 ;
    END
  END S4END[11]
  PIN S4END[12]
    DIRECTION INPUT ;
    USE SIGNAL ;
    ANTENNAGATEAREA 0.180700 ;
    PORT
      LAYER Metal2 ;
        RECT 152.920 271.760 153.320 272.160 ;
    END
  END S4END[12]
  PIN S4END[13]
    DIRECTION INPUT ;
    USE SIGNAL ;
    ANTENNAGATEAREA 0.180700 ;
    PORT
      LAYER Metal2 ;
        RECT 153.880 271.760 154.280 272.160 ;
    END
  END S4END[13]
  PIN S4END[14]
    DIRECTION INPUT ;
    USE SIGNAL ;
    ANTENNAGATEAREA 0.180700 ;
    PORT
      LAYER Metal2 ;
        RECT 154.840 271.760 155.240 272.160 ;
    END
  END S4END[14]
  PIN S4END[15]
    DIRECTION INPUT ;
    USE SIGNAL ;
    ANTENNAGATEAREA 0.180700 ;
    PORT
      LAYER Metal2 ;
        RECT 155.800 271.760 156.200 272.160 ;
    END
  END S4END[15]
  PIN S4END[1]
    DIRECTION INPUT ;
    USE SIGNAL ;
    ANTENNAGATEAREA 1.918800 ;
    PORT
      LAYER Metal2 ;
        RECT 142.360 271.760 142.760 272.160 ;
    END
  END S4END[1]
  PIN S4END[2]
    DIRECTION INPUT ;
    USE SIGNAL ;
    ANTENNAGATEAREA 1.492400 ;
    PORT
      LAYER Metal2 ;
        RECT 143.320 271.760 143.720 272.160 ;
    END
  END S4END[2]
  PIN S4END[3]
    DIRECTION INPUT ;
    USE SIGNAL ;
    ANTENNAGATEAREA 1.492400 ;
    PORT
      LAYER Metal2 ;
        RECT 144.280 271.760 144.680 272.160 ;
    END
  END S4END[3]
  PIN S4END[4]
    DIRECTION INPUT ;
    USE SIGNAL ;
    ANTENNAGATEAREA 0.180700 ;
    PORT
      LAYER Metal2 ;
        RECT 145.240 271.760 145.640 272.160 ;
    END
  END S4END[4]
  PIN S4END[5]
    DIRECTION INPUT ;
    USE SIGNAL ;
    ANTENNAGATEAREA 0.180700 ;
    PORT
      LAYER Metal2 ;
        RECT 146.200 271.760 146.600 272.160 ;
    END
  END S4END[5]
  PIN S4END[6]
    DIRECTION INPUT ;
    USE SIGNAL ;
    ANTENNAGATEAREA 0.180700 ;
    PORT
      LAYER Metal2 ;
        RECT 147.160 271.760 147.560 272.160 ;
    END
  END S4END[6]
  PIN S4END[7]
    DIRECTION INPUT ;
    USE SIGNAL ;
    ANTENNAGATEAREA 0.180700 ;
    PORT
      LAYER Metal2 ;
        RECT 148.120 271.760 148.520 272.160 ;
    END
  END S4END[7]
  PIN S4END[8]
    DIRECTION INPUT ;
    USE SIGNAL ;
    ANTENNAGATEAREA 0.180700 ;
    PORT
      LAYER Metal2 ;
        RECT 149.080 271.760 149.480 272.160 ;
    END
  END S4END[8]
  PIN S4END[9]
    DIRECTION INPUT ;
    USE SIGNAL ;
    ANTENNAGATEAREA 0.180700 ;
    PORT
      LAYER Metal2 ;
        RECT 150.040 271.760 150.440 272.160 ;
    END
  END S4END[9]
  PIN SS4BEG[0]
    DIRECTION OUTPUT ;
    USE SIGNAL ;
    ANTENNADIFFAREA 2.724000 ;
    PORT
      LAYER Metal2 ;
        RECT 171.160 0.000 171.560 0.400 ;
    END
  END SS4BEG[0]
  PIN SS4BEG[10]
    DIRECTION OUTPUT ;
    USE SIGNAL ;
    ANTENNADIFFAREA 2.724000 ;
    PORT
      LAYER Metal2 ;
        RECT 180.760 0.000 181.160 0.400 ;
    END
  END SS4BEG[10]
  PIN SS4BEG[11]
    DIRECTION OUTPUT ;
    USE SIGNAL ;
    ANTENNADIFFAREA 2.724000 ;
    PORT
      LAYER Metal2 ;
        RECT 181.720 0.000 182.120 0.400 ;
    END
  END SS4BEG[11]
  PIN SS4BEG[12]
    DIRECTION OUTPUT ;
    USE SIGNAL ;
    ANTENNADIFFAREA 2.724000 ;
    PORT
      LAYER Metal2 ;
        RECT 182.680 0.000 183.080 0.400 ;
    END
  END SS4BEG[12]
  PIN SS4BEG[13]
    DIRECTION OUTPUT ;
    USE SIGNAL ;
    ANTENNADIFFAREA 2.724000 ;
    PORT
      LAYER Metal2 ;
        RECT 183.640 0.000 184.040 0.400 ;
    END
  END SS4BEG[13]
  PIN SS4BEG[14]
    DIRECTION OUTPUT ;
    USE SIGNAL ;
    ANTENNADIFFAREA 2.724000 ;
    PORT
      LAYER Metal2 ;
        RECT 184.600 0.000 185.000 0.400 ;
    END
  END SS4BEG[14]
  PIN SS4BEG[15]
    DIRECTION OUTPUT ;
    USE SIGNAL ;
    ANTENNADIFFAREA 2.724000 ;
    PORT
      LAYER Metal2 ;
        RECT 185.560 0.000 185.960 0.400 ;
    END
  END SS4BEG[15]
  PIN SS4BEG[1]
    DIRECTION OUTPUT ;
    USE SIGNAL ;
    ANTENNADIFFAREA 2.724000 ;
    PORT
      LAYER Metal2 ;
        RECT 172.120 0.000 172.520 0.400 ;
    END
  END SS4BEG[1]
  PIN SS4BEG[2]
    DIRECTION OUTPUT ;
    USE SIGNAL ;
    ANTENNADIFFAREA 2.724000 ;
    PORT
      LAYER Metal2 ;
        RECT 173.080 0.000 173.480 0.400 ;
    END
  END SS4BEG[2]
  PIN SS4BEG[3]
    DIRECTION OUTPUT ;
    USE SIGNAL ;
    ANTENNADIFFAREA 2.724000 ;
    PORT
      LAYER Metal2 ;
        RECT 174.040 0.000 174.440 0.400 ;
    END
  END SS4BEG[3]
  PIN SS4BEG[4]
    DIRECTION OUTPUT ;
    USE SIGNAL ;
    ANTENNADIFFAREA 2.724000 ;
    PORT
      LAYER Metal2 ;
        RECT 175.000 0.000 175.400 0.400 ;
    END
  END SS4BEG[4]
  PIN SS4BEG[5]
    DIRECTION OUTPUT ;
    USE SIGNAL ;
    ANTENNADIFFAREA 2.724000 ;
    PORT
      LAYER Metal2 ;
        RECT 175.960 0.000 176.360 0.400 ;
    END
  END SS4BEG[5]
  PIN SS4BEG[6]
    DIRECTION OUTPUT ;
    USE SIGNAL ;
    ANTENNADIFFAREA 2.724000 ;
    PORT
      LAYER Metal2 ;
        RECT 176.920 0.000 177.320 0.400 ;
    END
  END SS4BEG[6]
  PIN SS4BEG[7]
    DIRECTION OUTPUT ;
    USE SIGNAL ;
    ANTENNADIFFAREA 2.724000 ;
    PORT
      LAYER Metal2 ;
        RECT 177.880 0.000 178.280 0.400 ;
    END
  END SS4BEG[7]
  PIN SS4BEG[8]
    DIRECTION OUTPUT ;
    USE SIGNAL ;
    ANTENNADIFFAREA 2.724000 ;
    PORT
      LAYER Metal2 ;
        RECT 178.840 0.000 179.240 0.400 ;
    END
  END SS4BEG[8]
  PIN SS4BEG[9]
    DIRECTION OUTPUT ;
    USE SIGNAL ;
    ANTENNADIFFAREA 2.724000 ;
    PORT
      LAYER Metal2 ;
        RECT 179.800 0.000 180.200 0.400 ;
    END
  END SS4BEG[9]
  PIN SS4END[0]
    DIRECTION INPUT ;
    USE SIGNAL ;
    ANTENNAGATEAREA 1.505400 ;
    PORT
      LAYER Metal2 ;
        RECT 171.160 271.760 171.560 272.160 ;
    END
  END SS4END[0]
  PIN SS4END[10]
    DIRECTION INPUT ;
    USE SIGNAL ;
    ANTENNAGATEAREA 0.180700 ;
    PORT
      LAYER Metal2 ;
        RECT 180.760 271.760 181.160 272.160 ;
    END
  END SS4END[10]
  PIN SS4END[11]
    DIRECTION INPUT ;
    USE SIGNAL ;
    ANTENNAGATEAREA 0.180700 ;
    PORT
      LAYER Metal2 ;
        RECT 181.720 271.760 182.120 272.160 ;
    END
  END SS4END[11]
  PIN SS4END[12]
    DIRECTION INPUT ;
    USE SIGNAL ;
    ANTENNAGATEAREA 0.180700 ;
    PORT
      LAYER Metal2 ;
        RECT 182.680 271.760 183.080 272.160 ;
    END
  END SS4END[12]
  PIN SS4END[13]
    DIRECTION INPUT ;
    USE SIGNAL ;
    ANTENNAGATEAREA 0.180700 ;
    PORT
      LAYER Metal2 ;
        RECT 183.640 271.760 184.040 272.160 ;
    END
  END SS4END[13]
  PIN SS4END[14]
    DIRECTION INPUT ;
    USE SIGNAL ;
    ANTENNAGATEAREA 0.180700 ;
    PORT
      LAYER Metal2 ;
        RECT 184.600 271.760 185.000 272.160 ;
    END
  END SS4END[14]
  PIN SS4END[15]
    DIRECTION INPUT ;
    USE SIGNAL ;
    ANTENNAGATEAREA 0.180700 ;
    PORT
      LAYER Metal2 ;
        RECT 185.560 271.760 185.960 272.160 ;
    END
  END SS4END[15]
  PIN SS4END[1]
    DIRECTION INPUT ;
    USE SIGNAL ;
    ANTENNAGATEAREA 1.918800 ;
    PORT
      LAYER Metal2 ;
        RECT 172.120 271.760 172.520 272.160 ;
    END
  END SS4END[1]
  PIN SS4END[2]
    DIRECTION INPUT ;
    USE SIGNAL ;
    ANTENNAGATEAREA 1.705600 ;
    PORT
      LAYER Metal2 ;
        RECT 173.080 271.760 173.480 272.160 ;
    END
  END SS4END[2]
  PIN SS4END[3]
    DIRECTION INPUT ;
    USE SIGNAL ;
    ANTENNAGATEAREA 1.492400 ;
    PORT
      LAYER Metal2 ;
        RECT 174.040 271.760 174.440 272.160 ;
    END
  END SS4END[3]
  PIN SS4END[4]
    DIRECTION INPUT ;
    USE SIGNAL ;
    ANTENNAGATEAREA 0.180700 ;
    PORT
      LAYER Metal2 ;
        RECT 175.000 271.760 175.400 272.160 ;
    END
  END SS4END[4]
  PIN SS4END[5]
    DIRECTION INPUT ;
    USE SIGNAL ;
    ANTENNAGATEAREA 0.180700 ;
    PORT
      LAYER Metal2 ;
        RECT 175.960 271.760 176.360 272.160 ;
    END
  END SS4END[5]
  PIN SS4END[6]
    DIRECTION INPUT ;
    USE SIGNAL ;
    ANTENNAGATEAREA 0.180700 ;
    PORT
      LAYER Metal2 ;
        RECT 176.920 271.760 177.320 272.160 ;
    END
  END SS4END[6]
  PIN SS4END[7]
    DIRECTION INPUT ;
    USE SIGNAL ;
    ANTENNAGATEAREA 0.180700 ;
    PORT
      LAYER Metal2 ;
        RECT 177.880 271.760 178.280 272.160 ;
    END
  END SS4END[7]
  PIN SS4END[8]
    DIRECTION INPUT ;
    USE SIGNAL ;
    ANTENNAGATEAREA 0.180700 ;
    PORT
      LAYER Metal2 ;
        RECT 178.840 271.760 179.240 272.160 ;
    END
  END SS4END[8]
  PIN SS4END[9]
    DIRECTION INPUT ;
    USE SIGNAL ;
    ANTENNAGATEAREA 0.180700 ;
    PORT
      LAYER Metal2 ;
        RECT 179.800 271.760 180.200 272.160 ;
    END
  END SS4END[9]
  PIN UserCLK
    DIRECTION INPUT ;
    USE SIGNAL ;
    ANTENNAGATEAREA 1.450800 ;
    PORT
      LAYER Metal3 ;
        RECT 0.000 203.500 0.400 203.900 ;
    END
  END UserCLK
  PIN UserCLKo
    DIRECTION OUTPUT ;
    USE SIGNAL ;
    ANTENNADIFFAREA 2.724000 ;
    PORT
      LAYER Metal3 ;
        RECT 232.880 203.500 233.280 203.900 ;
    END
  END UserCLKo
  PIN VGND
    DIRECTION INOUT ;
    USE GROUND ;
    PORT
      LAYER Metal4 ;
        RECT 13.940 0.000 14.940 272.160 ;
    END
    PORT
      LAYER Metal4 ;
        RECT 63.940 0.000 64.940 272.160 ;
    END
    PORT
      LAYER Metal4 ;
        RECT 113.940 0.000 114.940 272.160 ;
    END
    PORT
      LAYER Metal4 ;
        RECT 163.940 0.000 164.940 272.160 ;
    END
    PORT
      LAYER Metal4 ;
        RECT 213.940 0.000 214.940 272.160 ;
    END
  END VGND
  PIN VPWR
    DIRECTION INOUT ;
    USE POWER ;
    PORT
      LAYER Metal4 ;
        RECT 10.940 0.000 11.940 272.160 ;
    END
    PORT
      LAYER Metal4 ;
        RECT 60.940 0.000 61.940 272.160 ;
    END
    PORT
      LAYER Metal4 ;
        RECT 110.940 0.000 111.940 272.160 ;
    END
    PORT
      LAYER Metal4 ;
        RECT 160.940 0.000 161.940 272.160 ;
    END
    PORT
      LAYER Metal4 ;
        RECT 210.940 0.000 211.940 272.160 ;
    END
  END VPWR
  PIN W1BEG[0]
    DIRECTION OUTPUT ;
    USE SIGNAL ;
    ANTENNADIFFAREA 2.724000 ;
    PORT
      LAYER Metal3 ;
        RECT 0.000 102.700 0.400 103.100 ;
    END
  END W1BEG[0]
  PIN W1BEG[1]
    DIRECTION OUTPUT ;
    USE SIGNAL ;
    ANTENNADIFFAREA 2.724000 ;
    PORT
      LAYER Metal3 ;
        RECT 0.000 104.380 0.400 104.780 ;
    END
  END W1BEG[1]
  PIN W1BEG[2]
    DIRECTION OUTPUT ;
    USE SIGNAL ;
    ANTENNADIFFAREA 2.724000 ;
    PORT
      LAYER Metal3 ;
        RECT 0.000 106.060 0.400 106.460 ;
    END
  END W1BEG[2]
  PIN W1BEG[3]
    DIRECTION OUTPUT ;
    USE SIGNAL ;
    ANTENNADIFFAREA 2.724000 ;
    PORT
      LAYER Metal3 ;
        RECT 0.000 107.740 0.400 108.140 ;
    END
  END W1BEG[3]
  PIN W1END[0]
    DIRECTION INPUT ;
    USE SIGNAL ;
    ANTENNAGATEAREA 2.345200 ;
    PORT
      LAYER Metal3 ;
        RECT 232.880 102.700 233.280 103.100 ;
    END
  END W1END[0]
  PIN W1END[1]
    DIRECTION INPUT ;
    USE SIGNAL ;
    ANTENNAGATEAREA 1.918800 ;
    PORT
      LAYER Metal3 ;
        RECT 232.880 104.380 233.280 104.780 ;
    END
  END W1END[1]
  PIN W1END[2]
    DIRECTION INPUT ;
    USE SIGNAL ;
    ANTENNAGATEAREA 2.132000 ;
    PORT
      LAYER Metal3 ;
        RECT 232.880 106.060 233.280 106.460 ;
    END
  END W1END[2]
  PIN W1END[3]
    DIRECTION INPUT ;
    USE SIGNAL ;
    ANTENNAGATEAREA 1.066000 ;
    PORT
      LAYER Metal3 ;
        RECT 232.880 107.740 233.280 108.140 ;
    END
  END W1END[3]
  PIN W2BEG[0]
    DIRECTION OUTPUT ;
    USE SIGNAL ;
    ANTENNADIFFAREA 2.724000 ;
    PORT
      LAYER Metal3 ;
        RECT 0.000 111.940 0.400 112.340 ;
    END
  END W2BEG[0]
  PIN W2BEG[1]
    DIRECTION OUTPUT ;
    USE SIGNAL ;
    ANTENNADIFFAREA 2.724000 ;
    PORT
      LAYER Metal3 ;
        RECT 0.000 113.620 0.400 114.020 ;
    END
  END W2BEG[1]
  PIN W2BEG[2]
    DIRECTION OUTPUT ;
    USE SIGNAL ;
    ANTENNADIFFAREA 2.724000 ;
    PORT
      LAYER Metal3 ;
        RECT 0.000 115.300 0.400 115.700 ;
    END
  END W2BEG[2]
  PIN W2BEG[3]
    DIRECTION OUTPUT ;
    USE SIGNAL ;
    ANTENNADIFFAREA 2.724000 ;
    PORT
      LAYER Metal3 ;
        RECT 0.000 116.980 0.400 117.380 ;
    END
  END W2BEG[3]
  PIN W2BEG[4]
    DIRECTION OUTPUT ;
    USE SIGNAL ;
    ANTENNADIFFAREA 2.724000 ;
    PORT
      LAYER Metal3 ;
        RECT 0.000 118.660 0.400 119.060 ;
    END
  END W2BEG[4]
  PIN W2BEG[5]
    DIRECTION OUTPUT ;
    USE SIGNAL ;
    ANTENNADIFFAREA 2.724000 ;
    PORT
      LAYER Metal3 ;
        RECT 0.000 120.340 0.400 120.740 ;
    END
  END W2BEG[5]
  PIN W2BEG[6]
    DIRECTION OUTPUT ;
    USE SIGNAL ;
    ANTENNADIFFAREA 2.724000 ;
    PORT
      LAYER Metal3 ;
        RECT 0.000 122.020 0.400 122.420 ;
    END
  END W2BEG[6]
  PIN W2BEG[7]
    DIRECTION OUTPUT ;
    USE SIGNAL ;
    ANTENNADIFFAREA 2.724000 ;
    PORT
      LAYER Metal3 ;
        RECT 0.000 123.700 0.400 124.100 ;
    END
  END W2BEG[7]
  PIN W2BEGb[0]
    DIRECTION OUTPUT ;
    USE SIGNAL ;
    ANTENNADIFFAREA 2.724000 ;
    PORT
      LAYER Metal3 ;
        RECT 0.000 128.740 0.400 129.140 ;
    END
  END W2BEGb[0]
  PIN W2BEGb[1]
    DIRECTION OUTPUT ;
    USE SIGNAL ;
    ANTENNADIFFAREA 2.724000 ;
    PORT
      LAYER Metal3 ;
        RECT 0.000 130.420 0.400 130.820 ;
    END
  END W2BEGb[1]
  PIN W2BEGb[2]
    DIRECTION OUTPUT ;
    USE SIGNAL ;
    ANTENNADIFFAREA 2.724000 ;
    PORT
      LAYER Metal3 ;
        RECT 0.000 132.100 0.400 132.500 ;
    END
  END W2BEGb[2]
  PIN W2BEGb[3]
    DIRECTION OUTPUT ;
    USE SIGNAL ;
    ANTENNADIFFAREA 2.724000 ;
    PORT
      LAYER Metal3 ;
        RECT 0.000 133.780 0.400 134.180 ;
    END
  END W2BEGb[3]
  PIN W2BEGb[4]
    DIRECTION OUTPUT ;
    USE SIGNAL ;
    ANTENNADIFFAREA 2.724000 ;
    PORT
      LAYER Metal3 ;
        RECT 0.000 135.460 0.400 135.860 ;
    END
  END W2BEGb[4]
  PIN W2BEGb[5]
    DIRECTION OUTPUT ;
    USE SIGNAL ;
    ANTENNADIFFAREA 2.724000 ;
    PORT
      LAYER Metal3 ;
        RECT 0.000 137.140 0.400 137.540 ;
    END
  END W2BEGb[5]
  PIN W2BEGb[6]
    DIRECTION OUTPUT ;
    USE SIGNAL ;
    ANTENNADIFFAREA 2.724000 ;
    PORT
      LAYER Metal3 ;
        RECT 0.000 138.820 0.400 139.220 ;
    END
  END W2BEGb[6]
  PIN W2BEGb[7]
    DIRECTION OUTPUT ;
    USE SIGNAL ;
    ANTENNADIFFAREA 2.724000 ;
    PORT
      LAYER Metal3 ;
        RECT 0.000 140.500 0.400 140.900 ;
    END
  END W2BEGb[7]
  PIN W2END[0]
    DIRECTION INPUT ;
    USE SIGNAL ;
    ANTENNAGATEAREA 1.305200 ;
    PORT
      LAYER Metal3 ;
        RECT 232.880 128.740 233.280 129.140 ;
    END
  END W2END[0]
  PIN W2END[1]
    DIRECTION INPUT ;
    USE SIGNAL ;
    ANTENNAGATEAREA 0.852800 ;
    PORT
      LAYER Metal3 ;
        RECT 232.880 130.420 233.280 130.820 ;
    END
  END W2END[1]
  PIN W2END[2]
    DIRECTION INPUT ;
    USE SIGNAL ;
    ANTENNAGATEAREA 1.279200 ;
    PORT
      LAYER Metal3 ;
        RECT 232.880 132.100 233.280 132.500 ;
    END
  END W2END[2]
  PIN W2END[3]
    DIRECTION INPUT ;
    USE SIGNAL ;
    ANTENNAGATEAREA 1.705600 ;
    PORT
      LAYER Metal3 ;
        RECT 232.880 133.780 233.280 134.180 ;
    END
  END W2END[3]
  PIN W2END[4]
    DIRECTION INPUT ;
    USE SIGNAL ;
    ANTENNAGATEAREA 1.705600 ;
    PORT
      LAYER Metal3 ;
        RECT 232.880 135.460 233.280 135.860 ;
    END
  END W2END[4]
  PIN W2END[5]
    DIRECTION INPUT ;
    USE SIGNAL ;
    ANTENNAGATEAREA 1.492400 ;
    PORT
      LAYER Metal3 ;
        RECT 232.880 137.140 233.280 137.540 ;
    END
  END W2END[5]
  PIN W2END[6]
    DIRECTION INPUT ;
    USE SIGNAL ;
    ANTENNAGATEAREA 1.505400 ;
    PORT
      LAYER Metal3 ;
        RECT 232.880 138.820 233.280 139.220 ;
    END
  END W2END[6]
  PIN W2END[7]
    DIRECTION INPUT ;
    USE SIGNAL ;
    ANTENNAGATEAREA 0.852800 ;
    PORT
      LAYER Metal3 ;
        RECT 232.880 140.500 233.280 140.900 ;
    END
  END W2END[7]
  PIN W2MID[0]
    DIRECTION INPUT ;
    USE SIGNAL ;
    ANTENNAGATEAREA 1.459900 ;
    PORT
      LAYER Metal3 ;
        RECT 232.880 111.940 233.280 112.340 ;
    END
  END W2MID[0]
  PIN W2MID[1]
    DIRECTION INPUT ;
    USE SIGNAL ;
    ANTENNAGATEAREA 1.673100 ;
    PORT
      LAYER Metal3 ;
        RECT 232.880 113.620 233.280 114.020 ;
    END
  END W2MID[1]
  PIN W2MID[2]
    DIRECTION INPUT ;
    USE SIGNAL ;
    ANTENNAGATEAREA 1.459900 ;
    ANTENNADIFFAREA 16.123199 ;
    PORT
      LAYER Metal3 ;
        RECT 232.880 115.300 233.280 115.700 ;
    END
  END W2MID[2]
  PIN W2MID[3]
    DIRECTION INPUT ;
    USE SIGNAL ;
    ANTENNAGATEAREA 1.459900 ;
    PORT
      LAYER Metal3 ;
        RECT 232.880 116.980 233.280 117.380 ;
    END
  END W2MID[3]
  PIN W2MID[4]
    DIRECTION INPUT ;
    USE SIGNAL ;
    ANTENNAGATEAREA 1.673100 ;
    PORT
      LAYER Metal3 ;
        RECT 232.880 118.660 233.280 119.060 ;
    END
  END W2MID[4]
  PIN W2MID[5]
    DIRECTION INPUT ;
    USE SIGNAL ;
    ANTENNAGATEAREA 1.886300 ;
    PORT
      LAYER Metal3 ;
        RECT 232.880 120.340 233.280 120.740 ;
    END
  END W2MID[5]
  PIN W2MID[6]
    DIRECTION INPUT ;
    USE SIGNAL ;
    ANTENNAGATEAREA 1.459900 ;
    ANTENNADIFFAREA 16.123199 ;
    PORT
      LAYER Metal3 ;
        RECT 232.880 122.020 233.280 122.420 ;
    END
  END W2MID[6]
  PIN W2MID[7]
    DIRECTION INPUT ;
    USE SIGNAL ;
    ANTENNAGATEAREA 2.099500 ;
    PORT
      LAYER Metal3 ;
        RECT 232.880 123.700 233.280 124.100 ;
    END
  END W2MID[7]
  PIN W6BEG[0]
    DIRECTION OUTPUT ;
    USE SIGNAL ;
    ANTENNADIFFAREA 2.724000 ;
    PORT
      LAYER Metal3 ;
        RECT 0.000 179.980 0.400 180.380 ;
    END
  END W6BEG[0]
  PIN W6BEG[10]
    DIRECTION OUTPUT ;
    USE SIGNAL ;
    ANTENNADIFFAREA 2.724000 ;
    PORT
      LAYER Metal3 ;
        RECT 0.000 196.780 0.400 197.180 ;
    END
  END W6BEG[10]
  PIN W6BEG[11]
    DIRECTION OUTPUT ;
    USE SIGNAL ;
    ANTENNADIFFAREA 2.724000 ;
    PORT
      LAYER Metal3 ;
        RECT 0.000 198.460 0.400 198.860 ;
    END
  END W6BEG[11]
  PIN W6BEG[1]
    DIRECTION OUTPUT ;
    USE SIGNAL ;
    ANTENNADIFFAREA 2.724000 ;
    PORT
      LAYER Metal3 ;
        RECT 0.000 181.660 0.400 182.060 ;
    END
  END W6BEG[1]
  PIN W6BEG[2]
    DIRECTION OUTPUT ;
    USE SIGNAL ;
    ANTENNADIFFAREA 2.724000 ;
    PORT
      LAYER Metal3 ;
        RECT 0.000 183.340 0.400 183.740 ;
    END
  END W6BEG[2]
  PIN W6BEG[3]
    DIRECTION OUTPUT ;
    USE SIGNAL ;
    ANTENNADIFFAREA 2.724000 ;
    PORT
      LAYER Metal3 ;
        RECT 0.000 185.020 0.400 185.420 ;
    END
  END W6BEG[3]
  PIN W6BEG[4]
    DIRECTION OUTPUT ;
    USE SIGNAL ;
    ANTENNADIFFAREA 2.724000 ;
    PORT
      LAYER Metal3 ;
        RECT 0.000 186.700 0.400 187.100 ;
    END
  END W6BEG[4]
  PIN W6BEG[5]
    DIRECTION OUTPUT ;
    USE SIGNAL ;
    ANTENNADIFFAREA 2.724000 ;
    PORT
      LAYER Metal3 ;
        RECT 0.000 188.380 0.400 188.780 ;
    END
  END W6BEG[5]
  PIN W6BEG[6]
    DIRECTION OUTPUT ;
    USE SIGNAL ;
    ANTENNADIFFAREA 2.724000 ;
    PORT
      LAYER Metal3 ;
        RECT 0.000 190.060 0.400 190.460 ;
    END
  END W6BEG[6]
  PIN W6BEG[7]
    DIRECTION OUTPUT ;
    USE SIGNAL ;
    ANTENNADIFFAREA 2.724000 ;
    PORT
      LAYER Metal3 ;
        RECT 0.000 191.740 0.400 192.140 ;
    END
  END W6BEG[7]
  PIN W6BEG[8]
    DIRECTION OUTPUT ;
    USE SIGNAL ;
    ANTENNADIFFAREA 2.724000 ;
    PORT
      LAYER Metal3 ;
        RECT 0.000 193.420 0.400 193.820 ;
    END
  END W6BEG[8]
  PIN W6BEG[9]
    DIRECTION OUTPUT ;
    USE SIGNAL ;
    ANTENNADIFFAREA 2.724000 ;
    PORT
      LAYER Metal3 ;
        RECT 0.000 195.100 0.400 195.500 ;
    END
  END W6BEG[9]
  PIN W6END[0]
    DIRECTION INPUT ;
    USE SIGNAL ;
    ANTENNAGATEAREA 1.718600 ;
    PORT
      LAYER Metal3 ;
        RECT 232.880 179.980 233.280 180.380 ;
    END
  END W6END[0]
  PIN W6END[10]
    DIRECTION INPUT ;
    USE SIGNAL ;
    ANTENNAGATEAREA 0.180700 ;
    PORT
      LAYER Metal3 ;
        RECT 232.880 196.780 233.280 197.180 ;
    END
  END W6END[10]
  PIN W6END[11]
    DIRECTION INPUT ;
    USE SIGNAL ;
    ANTENNAGATEAREA 0.180700 ;
    PORT
      LAYER Metal3 ;
        RECT 232.880 198.460 233.280 198.860 ;
    END
  END W6END[11]
  PIN W6END[1]
    DIRECTION INPUT ;
    USE SIGNAL ;
    ANTENNAGATEAREA 2.145000 ;
    PORT
      LAYER Metal3 ;
        RECT 232.880 181.660 233.280 182.060 ;
    END
  END W6END[1]
  PIN W6END[2]
    DIRECTION INPUT ;
    USE SIGNAL ;
    ANTENNAGATEAREA 0.180700 ;
    PORT
      LAYER Metal3 ;
        RECT 232.880 183.340 233.280 183.740 ;
    END
  END W6END[2]
  PIN W6END[3]
    DIRECTION INPUT ;
    USE SIGNAL ;
    ANTENNAGATEAREA 0.180700 ;
    PORT
      LAYER Metal3 ;
        RECT 232.880 185.020 233.280 185.420 ;
    END
  END W6END[3]
  PIN W6END[4]
    DIRECTION INPUT ;
    USE SIGNAL ;
    ANTENNAGATEAREA 0.180700 ;
    PORT
      LAYER Metal3 ;
        RECT 232.880 186.700 233.280 187.100 ;
    END
  END W6END[4]
  PIN W6END[5]
    DIRECTION INPUT ;
    USE SIGNAL ;
    ANTENNAGATEAREA 0.180700 ;
    PORT
      LAYER Metal3 ;
        RECT 232.880 188.380 233.280 188.780 ;
    END
  END W6END[5]
  PIN W6END[6]
    DIRECTION INPUT ;
    USE SIGNAL ;
    ANTENNAGATEAREA 0.180700 ;
    PORT
      LAYER Metal3 ;
        RECT 232.880 190.060 233.280 190.460 ;
    END
  END W6END[6]
  PIN W6END[7]
    DIRECTION INPUT ;
    USE SIGNAL ;
    ANTENNAGATEAREA 0.180700 ;
    PORT
      LAYER Metal3 ;
        RECT 232.880 191.740 233.280 192.140 ;
    END
  END W6END[7]
  PIN W6END[8]
    DIRECTION INPUT ;
    USE SIGNAL ;
    ANTENNAGATEAREA 0.180700 ;
    PORT
      LAYER Metal3 ;
        RECT 232.880 193.420 233.280 193.820 ;
    END
  END W6END[8]
  PIN W6END[9]
    DIRECTION INPUT ;
    USE SIGNAL ;
    ANTENNAGATEAREA 0.180700 ;
    PORT
      LAYER Metal3 ;
        RECT 232.880 195.100 233.280 195.500 ;
    END
  END W6END[9]
  PIN WW4BEG[0]
    DIRECTION OUTPUT ;
    USE SIGNAL ;
    ANTENNADIFFAREA 2.724000 ;
    PORT
      LAYER Metal3 ;
        RECT 0.000 147.220 0.400 147.620 ;
    END
  END WW4BEG[0]
  PIN WW4BEG[10]
    DIRECTION OUTPUT ;
    USE SIGNAL ;
    ANTENNADIFFAREA 2.724000 ;
    PORT
      LAYER Metal3 ;
        RECT 0.000 164.020 0.400 164.420 ;
    END
  END WW4BEG[10]
  PIN WW4BEG[11]
    DIRECTION OUTPUT ;
    USE SIGNAL ;
    ANTENNADIFFAREA 2.724000 ;
    PORT
      LAYER Metal3 ;
        RECT 0.000 165.700 0.400 166.100 ;
    END
  END WW4BEG[11]
  PIN WW4BEG[12]
    DIRECTION OUTPUT ;
    USE SIGNAL ;
    ANTENNADIFFAREA 2.724000 ;
    PORT
      LAYER Metal3 ;
        RECT 0.000 167.380 0.400 167.780 ;
    END
  END WW4BEG[12]
  PIN WW4BEG[13]
    DIRECTION OUTPUT ;
    USE SIGNAL ;
    ANTENNADIFFAREA 2.724000 ;
    PORT
      LAYER Metal3 ;
        RECT 0.000 169.060 0.400 169.460 ;
    END
  END WW4BEG[13]
  PIN WW4BEG[14]
    DIRECTION OUTPUT ;
    USE SIGNAL ;
    ANTENNADIFFAREA 2.724000 ;
    PORT
      LAYER Metal3 ;
        RECT 0.000 170.740 0.400 171.140 ;
    END
  END WW4BEG[14]
  PIN WW4BEG[15]
    DIRECTION OUTPUT ;
    USE SIGNAL ;
    ANTENNADIFFAREA 2.724000 ;
    PORT
      LAYER Metal3 ;
        RECT 0.000 172.420 0.400 172.820 ;
    END
  END WW4BEG[15]
  PIN WW4BEG[1]
    DIRECTION OUTPUT ;
    USE SIGNAL ;
    ANTENNADIFFAREA 2.724000 ;
    PORT
      LAYER Metal3 ;
        RECT 0.000 148.900 0.400 149.300 ;
    END
  END WW4BEG[1]
  PIN WW4BEG[2]
    DIRECTION OUTPUT ;
    USE SIGNAL ;
    ANTENNADIFFAREA 2.724000 ;
    PORT
      LAYER Metal3 ;
        RECT 0.000 150.580 0.400 150.980 ;
    END
  END WW4BEG[2]
  PIN WW4BEG[3]
    DIRECTION OUTPUT ;
    USE SIGNAL ;
    ANTENNADIFFAREA 2.724000 ;
    PORT
      LAYER Metal3 ;
        RECT 0.000 152.260 0.400 152.660 ;
    END
  END WW4BEG[3]
  PIN WW4BEG[4]
    DIRECTION OUTPUT ;
    USE SIGNAL ;
    ANTENNADIFFAREA 2.724000 ;
    PORT
      LAYER Metal3 ;
        RECT 0.000 153.940 0.400 154.340 ;
    END
  END WW4BEG[4]
  PIN WW4BEG[5]
    DIRECTION OUTPUT ;
    USE SIGNAL ;
    ANTENNADIFFAREA 2.724000 ;
    PORT
      LAYER Metal3 ;
        RECT 0.000 155.620 0.400 156.020 ;
    END
  END WW4BEG[5]
  PIN WW4BEG[6]
    DIRECTION OUTPUT ;
    USE SIGNAL ;
    ANTENNADIFFAREA 2.724000 ;
    PORT
      LAYER Metal3 ;
        RECT 0.000 157.300 0.400 157.700 ;
    END
  END WW4BEG[6]
  PIN WW4BEG[7]
    DIRECTION OUTPUT ;
    USE SIGNAL ;
    ANTENNADIFFAREA 2.724000 ;
    PORT
      LAYER Metal3 ;
        RECT 0.000 158.980 0.400 159.380 ;
    END
  END WW4BEG[7]
  PIN WW4BEG[8]
    DIRECTION OUTPUT ;
    USE SIGNAL ;
    ANTENNADIFFAREA 2.724000 ;
    PORT
      LAYER Metal3 ;
        RECT 0.000 160.660 0.400 161.060 ;
    END
  END WW4BEG[8]
  PIN WW4BEG[9]
    DIRECTION OUTPUT ;
    USE SIGNAL ;
    ANTENNADIFFAREA 2.724000 ;
    PORT
      LAYER Metal3 ;
        RECT 0.000 162.340 0.400 162.740 ;
    END
  END WW4BEG[9]
  PIN WW4END[0]
    DIRECTION INPUT ;
    USE SIGNAL ;
    ANTENNAGATEAREA 1.734200 ;
    PORT
      LAYER Metal3 ;
        RECT 232.880 147.220 233.280 147.620 ;
    END
  END WW4END[0]
  PIN WW4END[10]
    DIRECTION INPUT ;
    USE SIGNAL ;
    ANTENNAGATEAREA 0.180700 ;
    PORT
      LAYER Metal3 ;
        RECT 232.880 164.020 233.280 164.420 ;
    END
  END WW4END[10]
  PIN WW4END[11]
    DIRECTION INPUT ;
    USE SIGNAL ;
    ANTENNAGATEAREA 0.180700 ;
    PORT
      LAYER Metal3 ;
        RECT 232.880 165.700 233.280 166.100 ;
    END
  END WW4END[11]
  PIN WW4END[12]
    DIRECTION INPUT ;
    USE SIGNAL ;
    ANTENNAGATEAREA 0.180700 ;
    PORT
      LAYER Metal3 ;
        RECT 232.880 167.380 233.280 167.780 ;
    END
  END WW4END[12]
  PIN WW4END[13]
    DIRECTION INPUT ;
    USE SIGNAL ;
    ANTENNAGATEAREA 0.180700 ;
    PORT
      LAYER Metal3 ;
        RECT 232.880 169.060 233.280 169.460 ;
    END
  END WW4END[13]
  PIN WW4END[14]
    DIRECTION INPUT ;
    USE SIGNAL ;
    ANTENNAGATEAREA 0.180700 ;
    PORT
      LAYER Metal3 ;
        RECT 232.880 170.740 233.280 171.140 ;
    END
  END WW4END[14]
  PIN WW4END[15]
    DIRECTION INPUT ;
    USE SIGNAL ;
    ANTENNAGATEAREA 0.180700 ;
    PORT
      LAYER Metal3 ;
        RECT 232.880 172.420 233.280 172.820 ;
    END
  END WW4END[15]
  PIN WW4END[1]
    DIRECTION INPUT ;
    USE SIGNAL ;
    ANTENNAGATEAREA 1.705600 ;
    PORT
      LAYER Metal3 ;
        RECT 232.880 148.900 233.280 149.300 ;
    END
  END WW4END[1]
  PIN WW4END[2]
    DIRECTION INPUT ;
    USE SIGNAL ;
    ANTENNAGATEAREA 1.705600 ;
    PORT
      LAYER Metal3 ;
        RECT 232.880 150.580 233.280 150.980 ;
    END
  END WW4END[2]
  PIN WW4END[3]
    DIRECTION INPUT ;
    USE SIGNAL ;
    ANTENNAGATEAREA 1.279200 ;
    PORT
      LAYER Metal3 ;
        RECT 232.880 152.260 233.280 152.660 ;
    END
  END WW4END[3]
  PIN WW4END[4]
    DIRECTION INPUT ;
    USE SIGNAL ;
    ANTENNAGATEAREA 0.180700 ;
    PORT
      LAYER Metal3 ;
        RECT 232.880 153.940 233.280 154.340 ;
    END
  END WW4END[4]
  PIN WW4END[5]
    DIRECTION INPUT ;
    USE SIGNAL ;
    ANTENNAGATEAREA 0.180700 ;
    PORT
      LAYER Metal3 ;
        RECT 232.880 155.620 233.280 156.020 ;
    END
  END WW4END[5]
  PIN WW4END[6]
    DIRECTION INPUT ;
    USE SIGNAL ;
    ANTENNAGATEAREA 0.180700 ;
    PORT
      LAYER Metal3 ;
        RECT 232.880 157.300 233.280 157.700 ;
    END
  END WW4END[6]
  PIN WW4END[7]
    DIRECTION INPUT ;
    USE SIGNAL ;
    ANTENNAGATEAREA 0.180700 ;
    PORT
      LAYER Metal3 ;
        RECT 232.880 158.980 233.280 159.380 ;
    END
  END WW4END[7]
  PIN WW4END[8]
    DIRECTION INPUT ;
    USE SIGNAL ;
    ANTENNAGATEAREA 0.180700 ;
    PORT
      LAYER Metal3 ;
        RECT 232.880 160.660 233.280 161.060 ;
    END
  END WW4END[8]
  PIN WW4END[9]
    DIRECTION INPUT ;
    USE SIGNAL ;
    ANTENNAGATEAREA 0.180700 ;
    PORT
      LAYER Metal3 ;
        RECT 232.880 162.340 233.280 162.740 ;
    END
  END WW4END[9]
  OBS
      LAYER GatPoly ;
        RECT 1.440 3.630 231.840 268.530 ;
      LAYER Metal1 ;
        RECT 1.440 3.560 231.840 268.600 ;
      LAYER Metal2 ;
        RECT 0.375 271.550 1.030 271.885 ;
        RECT 1.850 271.550 2.950 271.885 ;
        RECT 3.770 271.550 4.870 271.885 ;
        RECT 5.690 271.550 6.790 271.885 ;
        RECT 7.610 271.550 11.590 271.885 ;
        RECT 12.410 271.550 12.550 271.885 ;
        RECT 13.370 271.550 13.510 271.885 ;
        RECT 14.330 271.550 14.470 271.885 ;
        RECT 15.290 271.550 15.430 271.885 ;
        RECT 16.250 271.550 16.390 271.885 ;
        RECT 17.210 271.550 17.350 271.885 ;
        RECT 18.170 271.550 18.310 271.885 ;
        RECT 19.130 271.550 25.990 271.885 ;
        RECT 26.810 271.550 26.950 271.885 ;
        RECT 27.770 271.550 27.910 271.885 ;
        RECT 28.730 271.550 28.870 271.885 ;
        RECT 29.690 271.550 29.830 271.885 ;
        RECT 30.650 271.550 30.790 271.885 ;
        RECT 31.610 271.550 31.750 271.885 ;
        RECT 32.570 271.550 32.710 271.885 ;
        RECT 33.530 271.550 44.230 271.885 ;
        RECT 45.050 271.550 45.190 271.885 ;
        RECT 46.010 271.550 46.150 271.885 ;
        RECT 46.970 271.550 47.110 271.885 ;
        RECT 47.930 271.550 48.070 271.885 ;
        RECT 48.890 271.550 49.030 271.885 ;
        RECT 49.850 271.550 49.990 271.885 ;
        RECT 50.810 271.550 50.950 271.885 ;
        RECT 51.770 271.550 51.910 271.885 ;
        RECT 52.730 271.550 52.870 271.885 ;
        RECT 53.690 271.550 53.830 271.885 ;
        RECT 54.650 271.550 54.790 271.885 ;
        RECT 55.610 271.550 55.750 271.885 ;
        RECT 56.570 271.550 56.710 271.885 ;
        RECT 57.530 271.550 57.670 271.885 ;
        RECT 58.490 271.550 58.630 271.885 ;
        RECT 59.450 271.550 73.990 271.885 ;
        RECT 74.810 271.550 74.950 271.885 ;
        RECT 75.770 271.550 75.910 271.885 ;
        RECT 76.730 271.550 76.870 271.885 ;
        RECT 77.690 271.550 77.830 271.885 ;
        RECT 78.650 271.550 78.790 271.885 ;
        RECT 79.610 271.550 79.750 271.885 ;
        RECT 80.570 271.550 80.710 271.885 ;
        RECT 81.530 271.550 81.670 271.885 ;
        RECT 82.490 271.550 82.630 271.885 ;
        RECT 83.450 271.550 83.590 271.885 ;
        RECT 84.410 271.550 84.550 271.885 ;
        RECT 85.370 271.550 85.510 271.885 ;
        RECT 86.330 271.550 86.470 271.885 ;
        RECT 87.290 271.550 87.430 271.885 ;
        RECT 88.250 271.550 88.390 271.885 ;
        RECT 89.210 271.550 97.030 271.885 ;
        RECT 97.850 271.550 98.950 271.885 ;
        RECT 99.770 271.550 100.870 271.885 ;
        RECT 101.690 271.550 102.790 271.885 ;
        RECT 103.610 271.550 104.710 271.885 ;
        RECT 105.530 271.550 106.630 271.885 ;
        RECT 107.450 271.550 108.550 271.885 ;
        RECT 109.370 271.550 110.470 271.885 ;
        RECT 111.290 271.550 112.390 271.885 ;
        RECT 113.210 271.550 114.310 271.885 ;
        RECT 115.130 271.550 116.230 271.885 ;
        RECT 117.050 271.550 118.150 271.885 ;
        RECT 118.970 271.550 122.950 271.885 ;
        RECT 123.770 271.550 123.910 271.885 ;
        RECT 124.730 271.550 124.870 271.885 ;
        RECT 125.690 271.550 125.830 271.885 ;
        RECT 126.650 271.550 126.790 271.885 ;
        RECT 127.610 271.550 127.750 271.885 ;
        RECT 128.570 271.550 128.710 271.885 ;
        RECT 129.530 271.550 129.670 271.885 ;
        RECT 130.490 271.550 141.190 271.885 ;
        RECT 142.010 271.550 142.150 271.885 ;
        RECT 142.970 271.550 143.110 271.885 ;
        RECT 143.930 271.550 144.070 271.885 ;
        RECT 144.890 271.550 145.030 271.885 ;
        RECT 145.850 271.550 145.990 271.885 ;
        RECT 146.810 271.550 146.950 271.885 ;
        RECT 147.770 271.550 147.910 271.885 ;
        RECT 148.730 271.550 148.870 271.885 ;
        RECT 149.690 271.550 149.830 271.885 ;
        RECT 150.650 271.550 150.790 271.885 ;
        RECT 151.610 271.550 151.750 271.885 ;
        RECT 152.570 271.550 152.710 271.885 ;
        RECT 153.530 271.550 153.670 271.885 ;
        RECT 154.490 271.550 154.630 271.885 ;
        RECT 155.450 271.550 155.590 271.885 ;
        RECT 156.410 271.550 170.950 271.885 ;
        RECT 171.770 271.550 171.910 271.885 ;
        RECT 172.730 271.550 172.870 271.885 ;
        RECT 173.690 271.550 173.830 271.885 ;
        RECT 174.650 271.550 174.790 271.885 ;
        RECT 175.610 271.550 175.750 271.885 ;
        RECT 176.570 271.550 176.710 271.885 ;
        RECT 177.530 271.550 177.670 271.885 ;
        RECT 178.490 271.550 178.630 271.885 ;
        RECT 179.450 271.550 179.590 271.885 ;
        RECT 180.410 271.550 180.550 271.885 ;
        RECT 181.370 271.550 181.510 271.885 ;
        RECT 182.330 271.550 182.470 271.885 ;
        RECT 183.290 271.550 183.430 271.885 ;
        RECT 184.250 271.550 184.390 271.885 ;
        RECT 185.210 271.550 185.350 271.885 ;
        RECT 186.170 271.550 193.990 271.885 ;
        RECT 194.810 271.550 204.550 271.885 ;
        RECT 205.370 271.550 205.510 271.885 ;
        RECT 206.330 271.550 206.470 271.885 ;
        RECT 207.290 271.550 207.430 271.885 ;
        RECT 208.250 271.550 208.390 271.885 ;
        RECT 209.210 271.550 209.350 271.885 ;
        RECT 210.170 271.550 210.310 271.885 ;
        RECT 211.130 271.550 211.270 271.885 ;
        RECT 212.090 271.550 212.230 271.885 ;
        RECT 213.050 271.550 213.190 271.885 ;
        RECT 214.010 271.550 214.150 271.885 ;
        RECT 214.970 271.550 215.110 271.885 ;
        RECT 215.930 271.550 216.070 271.885 ;
        RECT 216.890 271.550 217.030 271.885 ;
        RECT 217.850 271.550 217.990 271.885 ;
        RECT 218.810 271.550 218.950 271.885 ;
        RECT 219.770 271.550 219.910 271.885 ;
        RECT 220.730 271.550 220.870 271.885 ;
        RECT 221.690 271.550 221.830 271.885 ;
        RECT 222.650 271.550 222.790 271.885 ;
        RECT 223.610 271.550 232.905 271.885 ;
        RECT 0.375 0.610 232.905 271.550 ;
        RECT 0.375 0.275 1.030 0.610 ;
        RECT 1.850 0.275 2.950 0.610 ;
        RECT 3.770 0.275 4.870 0.610 ;
        RECT 5.690 0.275 6.790 0.610 ;
        RECT 7.610 0.275 11.590 0.610 ;
        RECT 12.410 0.275 12.550 0.610 ;
        RECT 13.370 0.275 13.510 0.610 ;
        RECT 14.330 0.275 14.470 0.610 ;
        RECT 15.290 0.275 15.430 0.610 ;
        RECT 16.250 0.275 16.390 0.610 ;
        RECT 17.210 0.275 17.350 0.610 ;
        RECT 18.170 0.275 18.310 0.610 ;
        RECT 19.130 0.275 25.990 0.610 ;
        RECT 26.810 0.275 26.950 0.610 ;
        RECT 27.770 0.275 27.910 0.610 ;
        RECT 28.730 0.275 28.870 0.610 ;
        RECT 29.690 0.275 29.830 0.610 ;
        RECT 30.650 0.275 30.790 0.610 ;
        RECT 31.610 0.275 31.750 0.610 ;
        RECT 32.570 0.275 32.710 0.610 ;
        RECT 33.530 0.275 44.230 0.610 ;
        RECT 45.050 0.275 45.190 0.610 ;
        RECT 46.010 0.275 46.150 0.610 ;
        RECT 46.970 0.275 47.110 0.610 ;
        RECT 47.930 0.275 48.070 0.610 ;
        RECT 48.890 0.275 49.030 0.610 ;
        RECT 49.850 0.275 49.990 0.610 ;
        RECT 50.810 0.275 50.950 0.610 ;
        RECT 51.770 0.275 51.910 0.610 ;
        RECT 52.730 0.275 52.870 0.610 ;
        RECT 53.690 0.275 53.830 0.610 ;
        RECT 54.650 0.275 54.790 0.610 ;
        RECT 55.610 0.275 55.750 0.610 ;
        RECT 56.570 0.275 56.710 0.610 ;
        RECT 57.530 0.275 57.670 0.610 ;
        RECT 58.490 0.275 58.630 0.610 ;
        RECT 59.450 0.275 73.990 0.610 ;
        RECT 74.810 0.275 74.950 0.610 ;
        RECT 75.770 0.275 75.910 0.610 ;
        RECT 76.730 0.275 76.870 0.610 ;
        RECT 77.690 0.275 77.830 0.610 ;
        RECT 78.650 0.275 78.790 0.610 ;
        RECT 79.610 0.275 79.750 0.610 ;
        RECT 80.570 0.275 80.710 0.610 ;
        RECT 81.530 0.275 81.670 0.610 ;
        RECT 82.490 0.275 82.630 0.610 ;
        RECT 83.450 0.275 83.590 0.610 ;
        RECT 84.410 0.275 84.550 0.610 ;
        RECT 85.370 0.275 85.510 0.610 ;
        RECT 86.330 0.275 86.470 0.610 ;
        RECT 87.290 0.275 87.430 0.610 ;
        RECT 88.250 0.275 88.390 0.610 ;
        RECT 89.210 0.275 97.030 0.610 ;
        RECT 97.850 0.275 98.950 0.610 ;
        RECT 99.770 0.275 100.870 0.610 ;
        RECT 101.690 0.275 102.790 0.610 ;
        RECT 103.610 0.275 104.710 0.610 ;
        RECT 105.530 0.275 106.630 0.610 ;
        RECT 107.450 0.275 108.550 0.610 ;
        RECT 109.370 0.275 110.470 0.610 ;
        RECT 111.290 0.275 112.390 0.610 ;
        RECT 113.210 0.275 114.310 0.610 ;
        RECT 115.130 0.275 116.230 0.610 ;
        RECT 117.050 0.275 118.150 0.610 ;
        RECT 118.970 0.275 122.950 0.610 ;
        RECT 123.770 0.275 123.910 0.610 ;
        RECT 124.730 0.275 124.870 0.610 ;
        RECT 125.690 0.275 125.830 0.610 ;
        RECT 126.650 0.275 126.790 0.610 ;
        RECT 127.610 0.275 127.750 0.610 ;
        RECT 128.570 0.275 128.710 0.610 ;
        RECT 129.530 0.275 129.670 0.610 ;
        RECT 130.490 0.275 141.190 0.610 ;
        RECT 142.010 0.275 142.150 0.610 ;
        RECT 142.970 0.275 143.110 0.610 ;
        RECT 143.930 0.275 144.070 0.610 ;
        RECT 144.890 0.275 145.030 0.610 ;
        RECT 145.850 0.275 145.990 0.610 ;
        RECT 146.810 0.275 146.950 0.610 ;
        RECT 147.770 0.275 147.910 0.610 ;
        RECT 148.730 0.275 148.870 0.610 ;
        RECT 149.690 0.275 149.830 0.610 ;
        RECT 150.650 0.275 150.790 0.610 ;
        RECT 151.610 0.275 151.750 0.610 ;
        RECT 152.570 0.275 152.710 0.610 ;
        RECT 153.530 0.275 153.670 0.610 ;
        RECT 154.490 0.275 154.630 0.610 ;
        RECT 155.450 0.275 155.590 0.610 ;
        RECT 156.410 0.275 170.950 0.610 ;
        RECT 171.770 0.275 171.910 0.610 ;
        RECT 172.730 0.275 172.870 0.610 ;
        RECT 173.690 0.275 173.830 0.610 ;
        RECT 174.650 0.275 174.790 0.610 ;
        RECT 175.610 0.275 175.750 0.610 ;
        RECT 176.570 0.275 176.710 0.610 ;
        RECT 177.530 0.275 177.670 0.610 ;
        RECT 178.490 0.275 178.630 0.610 ;
        RECT 179.450 0.275 179.590 0.610 ;
        RECT 180.410 0.275 180.550 0.610 ;
        RECT 181.370 0.275 181.510 0.610 ;
        RECT 182.330 0.275 182.470 0.610 ;
        RECT 183.290 0.275 183.430 0.610 ;
        RECT 184.250 0.275 184.390 0.610 ;
        RECT 185.210 0.275 185.350 0.610 ;
        RECT 186.170 0.275 193.990 0.610 ;
        RECT 194.810 0.275 204.550 0.610 ;
        RECT 205.370 0.275 205.510 0.610 ;
        RECT 206.330 0.275 206.470 0.610 ;
        RECT 207.290 0.275 207.430 0.610 ;
        RECT 208.250 0.275 208.390 0.610 ;
        RECT 209.210 0.275 209.350 0.610 ;
        RECT 210.170 0.275 210.310 0.610 ;
        RECT 211.130 0.275 211.270 0.610 ;
        RECT 212.090 0.275 212.230 0.610 ;
        RECT 213.050 0.275 213.190 0.610 ;
        RECT 214.010 0.275 214.150 0.610 ;
        RECT 214.970 0.275 215.110 0.610 ;
        RECT 215.930 0.275 216.070 0.610 ;
        RECT 216.890 0.275 217.030 0.610 ;
        RECT 217.850 0.275 217.990 0.610 ;
        RECT 218.810 0.275 218.950 0.610 ;
        RECT 219.770 0.275 219.910 0.610 ;
        RECT 220.730 0.275 220.870 0.610 ;
        RECT 221.690 0.275 221.830 0.610 ;
        RECT 222.650 0.275 222.790 0.610 ;
        RECT 223.610 0.275 232.905 0.610 ;
      LAYER Metal3 ;
        RECT 0.335 264.590 232.945 271.845 ;
        RECT 0.610 263.770 232.670 264.590 ;
        RECT 0.335 262.910 232.945 263.770 ;
        RECT 0.610 262.090 232.670 262.910 ;
        RECT 0.335 261.230 232.945 262.090 ;
        RECT 0.610 260.410 232.670 261.230 ;
        RECT 0.335 259.550 232.945 260.410 ;
        RECT 0.610 258.730 232.670 259.550 ;
        RECT 0.335 257.870 232.945 258.730 ;
        RECT 0.610 257.050 232.670 257.870 ;
        RECT 0.335 256.190 232.945 257.050 ;
        RECT 0.610 255.370 232.670 256.190 ;
        RECT 0.335 254.510 232.945 255.370 ;
        RECT 0.610 253.690 232.670 254.510 ;
        RECT 0.335 252.830 232.945 253.690 ;
        RECT 0.610 252.010 232.670 252.830 ;
        RECT 0.335 251.150 232.945 252.010 ;
        RECT 0.610 250.330 232.670 251.150 ;
        RECT 0.335 249.470 232.945 250.330 ;
        RECT 0.610 248.650 232.670 249.470 ;
        RECT 0.335 247.790 232.945 248.650 ;
        RECT 0.610 246.970 232.670 247.790 ;
        RECT 0.335 246.110 232.945 246.970 ;
        RECT 0.610 245.290 232.670 246.110 ;
        RECT 0.335 244.430 232.945 245.290 ;
        RECT 0.610 243.610 232.670 244.430 ;
        RECT 0.335 242.750 232.945 243.610 ;
        RECT 0.610 241.930 232.670 242.750 ;
        RECT 0.335 241.070 232.945 241.930 ;
        RECT 0.610 240.250 232.670 241.070 ;
        RECT 0.335 239.390 232.945 240.250 ;
        RECT 0.610 238.570 232.670 239.390 ;
        RECT 0.335 237.710 232.945 238.570 ;
        RECT 0.610 236.890 232.670 237.710 ;
        RECT 0.335 236.030 232.945 236.890 ;
        RECT 0.610 235.210 232.670 236.030 ;
        RECT 0.335 234.350 232.945 235.210 ;
        RECT 0.610 233.530 232.670 234.350 ;
        RECT 0.335 232.670 232.945 233.530 ;
        RECT 0.610 231.850 232.670 232.670 ;
        RECT 0.335 230.990 232.945 231.850 ;
        RECT 0.610 230.170 232.670 230.990 ;
        RECT 0.335 229.310 232.945 230.170 ;
        RECT 0.610 228.490 232.670 229.310 ;
        RECT 0.335 227.630 232.945 228.490 ;
        RECT 0.610 226.810 232.670 227.630 ;
        RECT 0.335 225.950 232.945 226.810 ;
        RECT 0.610 225.130 232.670 225.950 ;
        RECT 0.335 224.270 232.945 225.130 ;
        RECT 0.610 223.450 232.670 224.270 ;
        RECT 0.335 222.590 232.945 223.450 ;
        RECT 0.610 221.770 232.670 222.590 ;
        RECT 0.335 220.910 232.945 221.770 ;
        RECT 0.610 220.090 232.670 220.910 ;
        RECT 0.335 219.230 232.945 220.090 ;
        RECT 0.610 218.410 232.670 219.230 ;
        RECT 0.335 217.550 232.945 218.410 ;
        RECT 0.610 216.730 232.670 217.550 ;
        RECT 0.335 215.870 232.945 216.730 ;
        RECT 0.610 215.050 232.670 215.870 ;
        RECT 0.335 214.190 232.945 215.050 ;
        RECT 0.610 213.370 232.670 214.190 ;
        RECT 0.335 212.510 232.945 213.370 ;
        RECT 0.610 211.690 232.670 212.510 ;
        RECT 0.335 204.110 232.945 211.690 ;
        RECT 0.610 203.290 232.670 204.110 ;
        RECT 0.335 199.070 232.945 203.290 ;
        RECT 0.610 198.250 232.670 199.070 ;
        RECT 0.335 197.390 232.945 198.250 ;
        RECT 0.610 196.570 232.670 197.390 ;
        RECT 0.335 195.710 232.945 196.570 ;
        RECT 0.610 194.890 232.670 195.710 ;
        RECT 0.335 194.030 232.945 194.890 ;
        RECT 0.610 193.210 232.670 194.030 ;
        RECT 0.335 192.350 232.945 193.210 ;
        RECT 0.610 191.530 232.670 192.350 ;
        RECT 0.335 190.670 232.945 191.530 ;
        RECT 0.610 189.850 232.670 190.670 ;
        RECT 0.335 188.990 232.945 189.850 ;
        RECT 0.610 188.170 232.670 188.990 ;
        RECT 0.335 187.310 232.945 188.170 ;
        RECT 0.610 186.490 232.670 187.310 ;
        RECT 0.335 185.630 232.945 186.490 ;
        RECT 0.610 184.810 232.670 185.630 ;
        RECT 0.335 183.950 232.945 184.810 ;
        RECT 0.610 183.130 232.670 183.950 ;
        RECT 0.335 182.270 232.945 183.130 ;
        RECT 0.610 181.450 232.670 182.270 ;
        RECT 0.335 180.590 232.945 181.450 ;
        RECT 0.610 179.770 232.670 180.590 ;
        RECT 0.335 173.030 232.945 179.770 ;
        RECT 0.610 172.210 232.670 173.030 ;
        RECT 0.335 171.350 232.945 172.210 ;
        RECT 0.610 170.530 232.670 171.350 ;
        RECT 0.335 169.670 232.945 170.530 ;
        RECT 0.610 168.850 232.670 169.670 ;
        RECT 0.335 167.990 232.945 168.850 ;
        RECT 0.610 167.170 232.670 167.990 ;
        RECT 0.335 166.310 232.945 167.170 ;
        RECT 0.610 165.490 232.670 166.310 ;
        RECT 0.335 164.630 232.945 165.490 ;
        RECT 0.610 163.810 232.670 164.630 ;
        RECT 0.335 162.950 232.945 163.810 ;
        RECT 0.610 162.130 232.670 162.950 ;
        RECT 0.335 161.270 232.945 162.130 ;
        RECT 0.610 160.450 232.670 161.270 ;
        RECT 0.335 159.590 232.945 160.450 ;
        RECT 0.610 158.770 232.670 159.590 ;
        RECT 0.335 157.910 232.945 158.770 ;
        RECT 0.610 157.090 232.670 157.910 ;
        RECT 0.335 156.230 232.945 157.090 ;
        RECT 0.610 155.410 232.670 156.230 ;
        RECT 0.335 154.550 232.945 155.410 ;
        RECT 0.610 153.730 232.670 154.550 ;
        RECT 0.335 152.870 232.945 153.730 ;
        RECT 0.610 152.050 232.670 152.870 ;
        RECT 0.335 151.190 232.945 152.050 ;
        RECT 0.610 150.370 232.670 151.190 ;
        RECT 0.335 149.510 232.945 150.370 ;
        RECT 0.610 148.690 232.670 149.510 ;
        RECT 0.335 147.830 232.945 148.690 ;
        RECT 0.610 147.010 232.670 147.830 ;
        RECT 0.335 141.110 232.945 147.010 ;
        RECT 0.610 140.290 232.670 141.110 ;
        RECT 0.335 139.430 232.945 140.290 ;
        RECT 0.610 138.610 232.670 139.430 ;
        RECT 0.335 137.750 232.945 138.610 ;
        RECT 0.610 136.930 232.670 137.750 ;
        RECT 0.335 136.070 232.945 136.930 ;
        RECT 0.610 135.250 232.670 136.070 ;
        RECT 0.335 134.390 232.945 135.250 ;
        RECT 0.610 133.570 232.670 134.390 ;
        RECT 0.335 132.710 232.945 133.570 ;
        RECT 0.610 131.890 232.670 132.710 ;
        RECT 0.335 131.030 232.945 131.890 ;
        RECT 0.610 130.210 232.670 131.030 ;
        RECT 0.335 129.350 232.945 130.210 ;
        RECT 0.610 128.530 232.670 129.350 ;
        RECT 0.335 124.310 232.945 128.530 ;
        RECT 0.610 123.490 232.670 124.310 ;
        RECT 0.335 122.630 232.945 123.490 ;
        RECT 0.610 121.810 232.670 122.630 ;
        RECT 0.335 120.950 232.945 121.810 ;
        RECT 0.610 120.130 232.670 120.950 ;
        RECT 0.335 119.270 232.945 120.130 ;
        RECT 0.610 118.450 232.670 119.270 ;
        RECT 0.335 117.590 232.945 118.450 ;
        RECT 0.610 116.770 232.670 117.590 ;
        RECT 0.335 115.910 232.945 116.770 ;
        RECT 0.610 115.090 232.670 115.910 ;
        RECT 0.335 114.230 232.945 115.090 ;
        RECT 0.610 113.410 232.670 114.230 ;
        RECT 0.335 112.550 232.945 113.410 ;
        RECT 0.610 111.730 232.670 112.550 ;
        RECT 0.335 108.350 232.945 111.730 ;
        RECT 0.610 107.530 232.670 108.350 ;
        RECT 0.335 106.670 232.945 107.530 ;
        RECT 0.610 105.850 232.670 106.670 ;
        RECT 0.335 104.990 232.945 105.850 ;
        RECT 0.610 104.170 232.670 104.990 ;
        RECT 0.335 103.310 232.945 104.170 ;
        RECT 0.610 102.490 232.670 103.310 ;
        RECT 0.335 98.270 232.945 102.490 ;
        RECT 0.610 97.450 232.670 98.270 ;
        RECT 0.335 96.590 232.945 97.450 ;
        RECT 0.610 95.770 232.670 96.590 ;
        RECT 0.335 94.910 232.945 95.770 ;
        RECT 0.610 94.090 232.670 94.910 ;
        RECT 0.335 93.230 232.945 94.090 ;
        RECT 0.610 92.410 232.670 93.230 ;
        RECT 0.335 91.550 232.945 92.410 ;
        RECT 0.610 90.730 232.670 91.550 ;
        RECT 0.335 89.870 232.945 90.730 ;
        RECT 0.610 89.050 232.670 89.870 ;
        RECT 0.335 88.190 232.945 89.050 ;
        RECT 0.610 87.370 232.670 88.190 ;
        RECT 0.335 86.510 232.945 87.370 ;
        RECT 0.610 85.690 232.670 86.510 ;
        RECT 0.335 84.830 232.945 85.690 ;
        RECT 0.610 84.010 232.670 84.830 ;
        RECT 0.335 83.150 232.945 84.010 ;
        RECT 0.610 82.330 232.670 83.150 ;
        RECT 0.335 81.470 232.945 82.330 ;
        RECT 0.610 80.650 232.670 81.470 ;
        RECT 0.335 79.790 232.945 80.650 ;
        RECT 0.610 78.970 232.670 79.790 ;
        RECT 0.335 72.230 232.945 78.970 ;
        RECT 0.610 71.410 232.670 72.230 ;
        RECT 0.335 70.550 232.945 71.410 ;
        RECT 0.610 69.730 232.670 70.550 ;
        RECT 0.335 68.870 232.945 69.730 ;
        RECT 0.610 68.050 232.670 68.870 ;
        RECT 0.335 67.190 232.945 68.050 ;
        RECT 0.610 66.370 232.670 67.190 ;
        RECT 0.335 65.510 232.945 66.370 ;
        RECT 0.610 64.690 232.670 65.510 ;
        RECT 0.335 63.830 232.945 64.690 ;
        RECT 0.610 63.010 232.670 63.830 ;
        RECT 0.335 62.150 232.945 63.010 ;
        RECT 0.610 61.330 232.670 62.150 ;
        RECT 0.335 60.470 232.945 61.330 ;
        RECT 0.610 59.650 232.670 60.470 ;
        RECT 0.335 58.790 232.945 59.650 ;
        RECT 0.610 57.970 232.670 58.790 ;
        RECT 0.335 57.110 232.945 57.970 ;
        RECT 0.610 56.290 232.670 57.110 ;
        RECT 0.335 55.430 232.945 56.290 ;
        RECT 0.610 54.610 232.670 55.430 ;
        RECT 0.335 53.750 232.945 54.610 ;
        RECT 0.610 52.930 232.670 53.750 ;
        RECT 0.335 52.070 232.945 52.930 ;
        RECT 0.610 51.250 232.670 52.070 ;
        RECT 0.335 50.390 232.945 51.250 ;
        RECT 0.610 49.570 232.670 50.390 ;
        RECT 0.335 48.710 232.945 49.570 ;
        RECT 0.610 47.890 232.670 48.710 ;
        RECT 0.335 47.030 232.945 47.890 ;
        RECT 0.610 46.210 232.670 47.030 ;
        RECT 0.335 40.310 232.945 46.210 ;
        RECT 0.610 39.490 232.670 40.310 ;
        RECT 0.335 38.630 232.945 39.490 ;
        RECT 0.610 37.810 232.670 38.630 ;
        RECT 0.335 36.950 232.945 37.810 ;
        RECT 0.610 36.130 232.670 36.950 ;
        RECT 0.335 35.270 232.945 36.130 ;
        RECT 0.610 34.450 232.670 35.270 ;
        RECT 0.335 33.590 232.945 34.450 ;
        RECT 0.610 32.770 232.670 33.590 ;
        RECT 0.335 31.910 232.945 32.770 ;
        RECT 0.610 31.090 232.670 31.910 ;
        RECT 0.335 30.230 232.945 31.090 ;
        RECT 0.610 29.410 232.670 30.230 ;
        RECT 0.335 28.550 232.945 29.410 ;
        RECT 0.610 27.730 232.670 28.550 ;
        RECT 0.335 23.510 232.945 27.730 ;
        RECT 0.610 22.690 232.670 23.510 ;
        RECT 0.335 21.830 232.945 22.690 ;
        RECT 0.610 21.010 232.670 21.830 ;
        RECT 0.335 20.150 232.945 21.010 ;
        RECT 0.610 19.330 232.670 20.150 ;
        RECT 0.335 18.470 232.945 19.330 ;
        RECT 0.610 17.650 232.670 18.470 ;
        RECT 0.335 16.790 232.945 17.650 ;
        RECT 0.610 15.970 232.670 16.790 ;
        RECT 0.335 15.110 232.945 15.970 ;
        RECT 0.610 14.290 232.670 15.110 ;
        RECT 0.335 13.430 232.945 14.290 ;
        RECT 0.610 12.610 232.670 13.430 ;
        RECT 0.335 11.750 232.945 12.610 ;
        RECT 0.610 10.930 232.670 11.750 ;
        RECT 0.335 7.550 232.945 10.930 ;
        RECT 0.610 6.730 232.670 7.550 ;
        RECT 0.335 5.870 232.945 6.730 ;
        RECT 0.610 5.050 232.670 5.870 ;
        RECT 0.335 4.190 232.945 5.050 ;
        RECT 0.610 3.370 232.670 4.190 ;
        RECT 0.335 2.510 232.945 3.370 ;
        RECT 0.610 1.690 232.670 2.510 ;
        RECT 0.335 0.315 232.945 1.690 ;
      LAYER Metal4 ;
        RECT 0.380 0.275 10.730 271.885 ;
        RECT 12.150 0.275 13.730 271.885 ;
        RECT 15.150 0.275 60.730 271.885 ;
        RECT 62.150 0.275 63.730 271.885 ;
        RECT 65.150 0.275 110.730 271.885 ;
        RECT 112.150 0.275 113.730 271.885 ;
        RECT 115.150 0.275 160.730 271.885 ;
        RECT 162.150 0.275 163.730 271.885 ;
        RECT 165.150 0.275 210.730 271.885 ;
        RECT 212.150 0.275 213.730 271.885 ;
        RECT 215.150 0.275 232.900 271.885 ;
  END
END FLUT51PSDM
END LIBRARY

